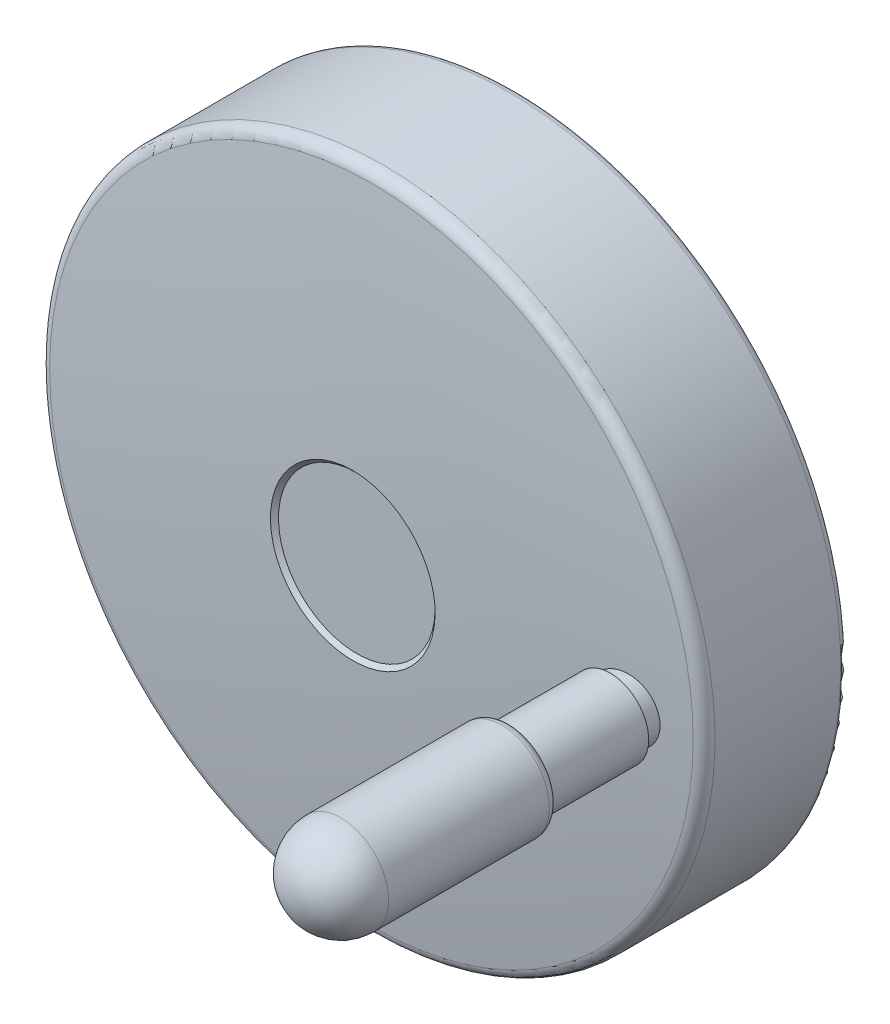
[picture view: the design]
ISO-10303-21;
HEADER;
FILE_DESCRIPTION(('STEP AP214'),'2;1');
FILE_NAME('part.step','',(''),(''),'','','');
FILE_SCHEMA(('AUTOMOTIVE_DESIGN { 1 0 10303 214 1 1 1 1 }'));
ENDSEC;
DATA;
#1=APPLICATION_CONTEXT('core data for automotive mechanical design processes');
#2=APPLICATION_PROTOCOL_DEFINITION('international standard','automotive_design',2000,#1);
#3=PRODUCT_CONTEXT('',#1,'mechanical');
#4=PRODUCT('Part','Part','',(#3));
#5=PRODUCT_RELATED_PRODUCT_CATEGORY('part','',(#4));
#6=PRODUCT_DEFINITION_FORMATION('','',#4);
#7=PRODUCT_DEFINITION_CONTEXT('part definition',#1,'design');
#8=PRODUCT_DEFINITION('design','',#6,#7);
#9=PRODUCT_DEFINITION_SHAPE('','',#8);
#10=(LENGTH_UNIT() NAMED_UNIT(*) SI_UNIT(.MILLI.,.METRE.));
#11=(NAMED_UNIT(*) PLANE_ANGLE_UNIT() SI_UNIT($,.RADIAN.));
#12=(NAMED_UNIT(*) SI_UNIT($,.STERADIAN.) SOLID_ANGLE_UNIT());
#13=UNCERTAINTY_MEASURE_WITH_UNIT(LENGTH_MEASURE(1.E-05),#10,'distance_accuracy_value','');
#14=(GEOMETRIC_REPRESENTATION_CONTEXT(3) GLOBAL_UNCERTAINTY_ASSIGNED_CONTEXT((#13)) GLOBAL_UNIT_ASSIGNED_CONTEXT((#10,
#11,#12)) REPRESENTATION_CONTEXT('',''));
#15=CARTESIAN_POINT('',(0.,0.,0.));
#16=DIRECTION('',(0.,0.,1.));
#17=DIRECTION('',(1.,0.,0.));
#18=AXIS2_PLACEMENT_3D('',#15,#16,#17);
#19=CARTESIAN_POINT('',(0.,0.,42.));
#20=DIRECTION('',(0.,0.,1.));
#21=DIRECTION('',(0.,1.,0.));
#22=AXIS2_PLACEMENT_3D('',#19,#20,#21);
#23=PLANE('',#22);
#24=CARTESIAN_POINT('',(49.,0.,42.));
#25=DIRECTION('',(0.,0.,1.));
#26=DIRECTION('',(0.,1.,0.));
#27=AXIS2_PLACEMENT_3D('',#24,#25,#26);
#28=CIRCLE('',#27,5.4375);
#29=CARTESIAN_POINT('',(49.,5.43749999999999,42.));
#30=VERTEX_POINT('',#29);
#31=EDGE_CURVE('E310',#30,#30,#28,.T.);
#32=ORIENTED_EDGE('',*,*,#31,.F.);
#33=EDGE_LOOP('',(#32));
#34=FACE_BOUND('',#33,.T.);
#35=CARTESIAN_POINT('',(49.,0.,42.));
#36=DIRECTION('',(0.,0.,-1.));
#37=DIRECTION('',(0.,-1.,0.));
#38=AXIS2_PLACEMENT_3D('',#35,#36,#37);
#39=CIRCLE('',#38,6.);
#40=CARTESIAN_POINT('',(49.,-6.,42.));
#41=VERTEX_POINT('',#40);
#42=EDGE_CURVE('E850',#41,#41,#39,.T.);
#43=ORIENTED_EDGE('',*,*,#42,.F.);
#44=EDGE_LOOP('',(#43));
#45=FACE_BOUND('',#44,.T.);
#46=ADVANCED_FACE('F15',(#34,#45),#23,.T.);
#47=CARTESIAN_POINT('',(49.,0.,38.));
#48=DIRECTION('',(0.,0.,-1.));
#49=DIRECTION('',(0.,-1.,0.));
#50=AXIS2_PLACEMENT_3D('',#47,#48,#49);
#51=CYLINDRICAL_SURFACE('',#50,6.);
#52=CARTESIAN_POINT('',(43.,0.,40.1107074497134));
#53=CARTESIAN_POINT('',(43.0000009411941,0.167835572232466,40.1107073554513));
#54=CARTESIAN_POINT('',(43.0070482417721,0.335701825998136,40.110000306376));
#55=CARTESIAN_POINT('',(43.035192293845,0.670274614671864,40.1071766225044));
#56=CARTESIAN_POINT('',(43.0562932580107,0.836980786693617,40.1050595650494));
#57=CARTESIAN_POINT('',(43.1124381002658,1.16828288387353,40.0994264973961));
#58=CARTESIAN_POINT('',(43.1475041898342,1.33287501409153,40.095908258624));
#59=CARTESIAN_POINT('',(43.2313557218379,1.65863013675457,40.0874951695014));
#60=CARTESIAN_POINT('',(43.2801521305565,1.81979027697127,40.0825992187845));
#61=CARTESIAN_POINT('',(43.3909930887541,2.13710869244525,40.0714778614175));
#62=CARTESIAN_POINT('',(43.4530131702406,2.29327560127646,40.065254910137));
#63=CARTESIAN_POINT('',(43.5899340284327,2.5998822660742,40.0515162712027));
#64=CARTESIAN_POINT('',(43.6648406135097,2.75031940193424,40.0440000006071));
#65=CARTESIAN_POINT('',(43.8269764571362,3.04434120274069,40.02773053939));
#66=CARTESIAN_POINT('',(43.9142064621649,3.18792545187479,40.0189772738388));
#67=CARTESIAN_POINT('',(44.1003135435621,3.46716202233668,40.0003014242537));
#68=CARTESIAN_POINT('',(44.1991854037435,3.60281785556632,39.9903793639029));
#69=CARTESIAN_POINT('',(44.4081943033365,3.8656949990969,39.9694040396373));
#70=CARTESIAN_POINT('',(44.5183626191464,3.99289119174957,39.958347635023));
#71=CARTESIAN_POINT('',(44.7488252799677,4.23741820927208,39.9352177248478));
#72=CARTESIAN_POINT('',(44.8691097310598,4.35475845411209,39.9231452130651));
#73=CARTESIAN_POINT('',(45.1190961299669,4.57895044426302,39.8980539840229));
#74=CARTESIAN_POINT('',(45.2488024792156,4.68579723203,39.8850348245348));
#75=CARTESIAN_POINT('',(45.5166911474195,4.88822582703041,39.8581445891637));
#76=CARTESIAN_POINT('',(45.6548754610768,4.9838049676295,39.8442733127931));
#77=CARTESIAN_POINT('',(45.9393374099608,5.16340606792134,39.8157170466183));
#78=CARTESIAN_POINT('',(46.0856479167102,5.24737544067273,39.8010287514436));
#79=CARTESIAN_POINT('',(46.3848184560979,5.40270708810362,39.7709932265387));
#80=CARTESIAN_POINT('',(46.5376808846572,5.47406470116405,39.7556457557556));
#81=CARTESIAN_POINT('',(46.8487652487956,5.60362101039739,39.7244111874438));
#82=CARTESIAN_POINT('',(47.006985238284,5.66182442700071,39.7085242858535));
#83=CARTESIAN_POINT('',(47.3277798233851,5.76472592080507,39.6763116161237));
#84=CARTESIAN_POINT('',(47.4903560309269,5.80941892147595,39.6599856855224));
#85=CARTESIAN_POINT('',(47.8193269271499,5.88511803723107,39.6269486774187));
#86=CARTESIAN_POINT('',(47.985734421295,5.91606794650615,39.6102363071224));
#87=CARTESIAN_POINT('',(48.3206243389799,5.96381333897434,39.5766014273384));
#88=CARTESIAN_POINT('',(48.4891076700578,5.98060239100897,39.5596788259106));
#89=CARTESIAN_POINT('',(48.82688464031,5.99988731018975,39.525750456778));
#90=CARTESIAN_POINT('',(48.996178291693,6.00238296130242,39.5087446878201));
#91=CARTESIAN_POINT('',(49.3342984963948,5.99306555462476,39.4747782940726));
#92=CARTESIAN_POINT('',(49.5031252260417,5.98125895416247,39.4578176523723));
#93=CARTESIAN_POINT('',(49.8396421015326,5.94337840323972,39.4240088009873));
#94=CARTESIAN_POINT('',(50.0073280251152,5.91726655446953,39.4071610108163));
#95=CARTESIAN_POINT('',(50.3398508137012,5.85094280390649,39.3737499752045));
#96=CARTESIAN_POINT('',(50.5046887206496,5.8107361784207,39.3571866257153));
#97=CARTESIAN_POINT('',(50.8304680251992,5.71648072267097,39.3244498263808));
#98=CARTESIAN_POINT('',(50.9914078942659,5.66242655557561,39.3082765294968));
#99=CARTESIAN_POINT('',(51.3081149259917,5.54088114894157,39.276448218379));
#100=CARTESIAN_POINT('',(51.4638839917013,5.47339491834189,39.2607930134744));
#101=CARTESIAN_POINT('',(51.7691010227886,5.32548779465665,39.2301164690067));
#102=CARTESIAN_POINT('',(51.9185528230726,5.24507489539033,39.2150947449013));
#103=CARTESIAN_POINT('',(52.2101278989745,5.07186615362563,39.1857866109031));
#104=CARTESIAN_POINT('',(52.352252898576,4.97907324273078,39.1715000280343));
#105=CARTESIAN_POINT('',(52.6281207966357,4.7817865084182,39.143768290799));
#106=CARTESIAN_POINT('',(52.7618676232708,4.67729823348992,39.1303227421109));
#107=CARTESIAN_POINT('',(53.0202101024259,4.45721140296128,39.1043506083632));
#108=CARTESIAN_POINT('',(53.144796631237,4.34160202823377,39.0918249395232));
#109=CARTESIAN_POINT('',(53.383236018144,4.10071161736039,39.0678518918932));
#110=CARTESIAN_POINT('',(53.4971338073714,3.97547550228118,39.0563999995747));
#111=CARTESIAN_POINT('',(53.7140344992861,3.71571286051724,39.0345909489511));
#112=CARTESIAN_POINT('',(53.8170324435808,3.58118215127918,39.0242342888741));
#113=CARTESIAN_POINT('',(54.0113136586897,3.30384601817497,39.0046983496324));
#114=CARTESIAN_POINT('',(54.1025977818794,3.16104119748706,38.9955189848));
#115=CARTESIAN_POINT('',(54.2727502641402,2.86823346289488,38.9784083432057));
#116=CARTESIAN_POINT('',(54.3516243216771,2.7182338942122,38.9704764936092));
#117=CARTESIAN_POINT('',(54.4961947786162,2.41253808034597,38.9559376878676));
#118=CARTESIAN_POINT('',(54.5619323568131,2.25686150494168,38.949326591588));
#119=CARTESIAN_POINT('',(54.680011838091,1.94060091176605,38.9374513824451));
#120=CARTESIAN_POINT('',(54.732364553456,1.78002097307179,38.9321861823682));
#121=CARTESIAN_POINT('',(54.8232839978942,1.45525129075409,38.9230421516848));
#122=CARTESIAN_POINT('',(54.8618729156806,1.29106781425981,38.9191610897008));
#123=CARTESIAN_POINT('',(54.9250903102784,0.960042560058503,38.9128029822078));
#124=CARTESIAN_POINT('',(54.9497230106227,0.793201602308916,38.9103255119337));
#125=CARTESIAN_POINT('',(54.9781855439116,0.521745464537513,38.9074628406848));
#126=CARTESIAN_POINT('',(54.9863633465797,0.417571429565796,38.9066403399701));
#127=CARTESIAN_POINT('',(54.997270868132,0.208935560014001,38.9055432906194));
#128=CARTESIAN_POINT('',(55.0000005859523,0.104473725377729,38.9052687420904));
#129=CARTESIAN_POINT('',(54.9999990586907,-0.167832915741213,38.905268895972));
#130=CARTESIAN_POINT('',(54.9929519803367,-0.335696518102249,38.9059776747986));
#131=CARTESIAN_POINT('',(54.964808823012,-0.670264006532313,38.9088082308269));
#132=CARTESIAN_POINT('',(54.9437085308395,-0.836967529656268,38.9109304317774));
#133=CARTESIAN_POINT('',(54.8875654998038,-1.16826434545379,38.9165770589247));
#134=CARTESIAN_POINT('',(54.8525005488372,-1.33285384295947,38.9201037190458));
#135=CARTESIAN_POINT('',(54.7686517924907,-1.65860370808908,38.9285366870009));
#136=CARTESIAN_POINT('',(54.7198570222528,-1.81976122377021,38.9334440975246));
#137=CARTESIAN_POINT('',(54.6090199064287,-2.13707433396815,38.9445910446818));
#138=CARTESIAN_POINT('',(54.5470020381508,-2.29323856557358,38.9508281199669));
#139=CARTESIAN_POINT('',(54.4100861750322,-2.59984000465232,38.9645972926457));
#140=CARTESIAN_POINT('',(54.3351823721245,-2.75027459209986,38.9721299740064));
#141=CARTESIAN_POINT('',(54.1730526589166,-3.04429152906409,38.9884340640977));
#142=CARTESIAN_POINT('',(54.0858260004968,-3.18787346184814,38.9972055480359));
#143=CARTESIAN_POINT('',(53.8997261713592,-3.46710571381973,39.0159191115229));
#144=CARTESIAN_POINT('',(53.8008582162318,-3.60275954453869,39.0258606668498));
#145=CARTESIAN_POINT('',(53.5918561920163,-3.86563494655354,39.0468759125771));
#146=CARTESIAN_POINT('',(53.4816906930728,-3.99283127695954,39.0579527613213));
#147=CARTESIAN_POINT('',(53.2512338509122,-4.23735881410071,39.081123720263));
#148=CARTESIAN_POINT('',(53.1309524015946,-4.35469944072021,39.0932168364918));
#149=CARTESIAN_POINT('',(52.8809721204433,-4.57889252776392,39.1183488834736));
#150=CARTESIAN_POINT('',(52.7512688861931,-4.68574002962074,39.131388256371));
#151=CARTESIAN_POINT('',(52.4833864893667,-4.88817043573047,39.158317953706));
#152=CARTESIAN_POINT('',(52.3452053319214,-4.9837506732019,39.1722084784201));
#153=CARTESIAN_POINT('',(52.0607466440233,-5.16335629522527,39.2008021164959));
#154=CARTESIAN_POINT('',(51.9144360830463,-5.24732884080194,39.2155085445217));
#155=CARTESIAN_POINT('',(51.6152650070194,-5.40266673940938,39.2455783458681));
#156=CARTESIAN_POINT('',(51.4624020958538,-5.47402743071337,39.2609419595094));
#157=CARTESIAN_POINT('',(51.1513162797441,-5.6035897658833,39.2922063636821));
#158=CARTESIAN_POINT('',(50.9930953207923,-5.66179612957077,39.3081069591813));
#159=CARTESIAN_POINT('',(50.6722982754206,-5.76470332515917,39.3403442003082));
#160=CARTESIAN_POINT('',(50.5097205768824,-5.80939908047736,39.3566810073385));
#161=CARTESIAN_POINT('',(50.1807455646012,-5.88510357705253,39.3897367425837));
#162=CARTESIAN_POINT('',(50.0143354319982,-5.91605606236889,39.4064569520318));
#163=CARTESIAN_POINT('',(49.679439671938,-5.96380613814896,39.4401041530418));
#164=CARTESIAN_POINT('',(49.5109531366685,-5.98059729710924,39.4570312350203));
#165=CARTESIAN_POINT('',(49.1731692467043,-5.99988585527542,39.4909650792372));
#166=CARTESIAN_POINT('',(49.0038718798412,-6.00238303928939,39.5079718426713));
#167=CARTESIAN_POINT('',(48.6657438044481,-5.99306802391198,39.5419367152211));
#168=CARTESIAN_POINT('',(48.4969129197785,-5.98126228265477,39.5588948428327));
#169=CARTESIAN_POINT('',(48.1603903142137,-5.94338301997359,39.5926949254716));
#170=CARTESIAN_POINT('',(47.992702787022,-5.91727184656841,39.6095364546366));
#171=CARTESIAN_POINT('',(47.6601764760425,-5.85094910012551,39.6429316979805));
#172=CARTESIAN_POINT('',(47.4953366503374,-5.81074280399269,39.6594855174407));
#173=CARTESIAN_POINT('',(47.1695533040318,-5.71648760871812,39.6922002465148));
#174=CARTESIAN_POINT('',(47.0086113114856,-5.66243337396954,39.7083610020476));
#175=CARTESIAN_POINT('',(46.6918999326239,-5.54088740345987,39.7401615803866));
#176=CARTESIAN_POINT('',(46.5361286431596,-5.47340067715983,39.7558015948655));
#177=CARTESIAN_POINT('',(46.230910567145,-5.32549377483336,39.7864452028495));
#178=CARTESIAN_POINT('',(46.0814598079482,-5.24508187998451,39.8014491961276));
#179=CARTESIAN_POINT('',(45.7898866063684,-5.07187528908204,39.8307201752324));
#180=CARTESIAN_POINT('',(45.6477624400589,-4.9790835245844,39.8449873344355));
#181=CARTESIAN_POINT('',(45.3718960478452,-4.78179924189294,39.8726790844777));
#182=CARTESIAN_POINT('',(45.2381498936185,-4.6773122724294,39.8861040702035));
#183=CARTESIAN_POINT('',(44.979808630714,-4.45722824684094,39.9120344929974));
#184=CARTESIAN_POINT('',(44.8552226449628,-4.34162037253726,39.9245390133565));
#185=CARTESIAN_POINT('',(44.6167849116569,-4.10073388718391,39.9484698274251));
#186=CARTESIAN_POINT('',(44.5028881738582,-3.97550025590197,39.9599006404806));
#187=CARTESIAN_POINT('',(44.285989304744,-3.71574294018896,39.9816681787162));
#188=CARTESIAN_POINT('',(44.1829921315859,-3.5812150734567,39.9920044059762));
#189=CARTESIAN_POINT('',(43.9887121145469,-3.30388496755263,40.0115007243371));
#190=CARTESIAN_POINT('',(43.8974284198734,-3.16108333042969,40.0206609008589));
#191=CARTESIAN_POINT('',(43.727276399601,-2.86828230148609,40.0377349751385));
#192=CARTESIAN_POINT('',(43.6484023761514,-2.71828625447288,40.0456494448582));
#193=CARTESIAN_POINT('',(43.5038303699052,-2.41259533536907,40.0601559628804));
#194=CARTESIAN_POINT('',(43.4380914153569,-2.25692003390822,40.0667521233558));
#195=CARTESIAN_POINT('',(43.3200090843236,-1.9406620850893,40.0786001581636));
#196=CARTESIAN_POINT('',(43.2676548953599,-1.78008351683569,40.083853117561));
#197=CARTESIAN_POINT('',(43.1767323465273,-1.45531658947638,40.0929757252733));
#198=CARTESIAN_POINT('',(43.1381418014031,-1.29113449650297,40.0968475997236));
#199=CARTESIAN_POINT('',(43.0749209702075,-0.960111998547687,40.1031906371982));
#200=CARTESIAN_POINT('',(43.0502864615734,-0.793272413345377,40.1056622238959));
#201=CARTESIAN_POINT('',(43.0218195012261,-0.521805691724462,40.108518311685));
#202=CARTESIAN_POINT('',(43.0136398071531,-0.417619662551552,40.1093389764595));
#203=CARTESIAN_POINT('',(43.0027297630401,-0.208959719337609,40.1104335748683));
#204=CARTESIAN_POINT('',(42.9999994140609,-0.104485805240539,40.1107075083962));
#205=CARTESIAN_POINT('',(43.,0.,40.1107074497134));
#206=B_SPLINE_CURVE_WITH_KNOTS('',3,(#52,#53,#54,#55,#56,#57,#58,#59,#60,#61,#62,#63,#64,#65,
#66,#67,#68,#69,#70,#71,#72,#73,#74,#75,#76,#77,#78,#79,#80,#81,#82,#83,#84,#85,#86,#87,#88,#89,
#90,#91,#92,#93,#94,#95,#96,#97,#98,#99,#100,#101,#102,#103,#104,#105,#106,#107,#108,#109,#110,
#111,#112,#113,#114,#115,#116,#117,#118,#119,#120,#121,#122,#123,#124,#125,#126,#127,#128,#129,
#130,#131,#132,#133,#134,#135,#136,#137,#138,#139,#140,#141,#142,#143,#144,#145,#146,#147,#148,
#149,#150,#151,#152,#153,#154,#155,#156,#157,#158,#159,#160,#161,#162,#163,#164,#165,#166,#167,
#168,#169,#170,#171,#172,#173,#174,#175,#176,#177,#178,#179,#180,#181,#182,#183,#184,#185,#186,
#187,#188,#189,#190,#191,#192,#193,#194,#195,#196,#197,#198,#199,#200,#201,#202,#203,#204,#205),
.UNSPECIFIED.,.T.,.F.,(4,2,2,2,2,2,2,2,2,2,2,2,2,2,2,2,2,2,2,2,2,2,2,2,2,2,2,2,2,2,2,2,2,2,2,2,
2,2,2,2,2,2,2,2,2,2,2,2,2,2,2,2,2,2,2,2,2,2,2,2,2,2,2,2,2,2,2,2,2,2,2,2,2,2,2,2,4),(0.,
0.50341075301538,1.00697247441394,1.51133832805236,2.01610816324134,2.51995199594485,
3.02402352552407,3.52812560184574,4.03200266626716,4.5373145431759,5.04213783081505,
5.54719848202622,6.05237842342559,6.55977646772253,7.06736166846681,7.57476443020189,
8.08235761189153,8.59200802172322,9.10188976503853,9.6117792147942,10.1214385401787,
10.6324546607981,11.1432796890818,11.6543018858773,12.1651338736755,12.6756511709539,
13.1860477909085,13.6962032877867,14.2068602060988,14.7152641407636,15.223898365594,
15.7324955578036,16.2408585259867,16.7476020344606,17.2539348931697,17.7594477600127,
18.2648075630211,18.5781689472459,18.8915303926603,19.3949331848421,19.8984869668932,
20.4028449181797,20.9076068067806,21.4114423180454,21.9155055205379,22.419599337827,
22.9234681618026,23.4287788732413,23.9336009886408,24.4386605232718,24.9438393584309,
25.4512469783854,25.9588417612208,26.4662541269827,26.9738569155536,27.4835187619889,
27.9934119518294,28.503312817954,29.0129835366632,29.5240022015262,30.0348297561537,
30.5458544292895,31.0566888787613,31.5671973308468,32.077585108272,32.587731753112,
33.0983797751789,33.6067718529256,34.1153942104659,34.6239796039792,35.1323307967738,
35.6390706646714,36.145399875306,36.6509092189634,37.1562655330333,37.4696631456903,
37.7830608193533),.UNSPECIFIED.);
#207=CARTESIAN_POINT('',(43.,0.,40.1107074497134));
#208=VERTEX_POINT('',#207);
#209=EDGE_CURVE('E337',#208,#208,#206,.T.);
#210=ORIENTED_EDGE('',*,*,#209,.F.);
#211=EDGE_LOOP('',(#210));
#212=FACE_BOUND('',#211,.T.);
#213=ORIENTED_EDGE('',*,*,#42,.T.);
#214=EDGE_LOOP('',(#213));
#215=FACE_BOUND('',#214,.T.);
#216=ADVANCED_FACE('F332',(#212,#215),#51,.T.);
#217=CARTESIAN_POINT('',(0.,0.,-448.281250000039));
#218=DIRECTION('',(-1.,0.,0.));
#219=DIRECTION('',(0.,0.,1.));
#220=AXIS2_PLACEMENT_3D('',#217,#218,#219);
#221=SPHERICAL_SURFACE('',#220,490.281250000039);
#222=CARTESIAN_POINT('',(0.,0.,38.2439407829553));
#223=DIRECTION('',(0.,0.,1.));
#224=DIRECTION('',(0.,1.,0.));
#225=AXIS2_PLACEMENT_3D('',#222,#223,#224);
#226=CIRCLE('',#225,60.571799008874);
#227=CARTESIAN_POINT('',(0.,60.571799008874,38.2439407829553));
#228=VERTEX_POINT('',#227);
#229=EDGE_CURVE('E304',#228,#228,#226,.T.);
#230=ORIENTED_EDGE('',*,*,#229,.T.);
#231=EDGE_LOOP('',(#230));
#232=FACE_BOUND('',#231,.T.);
#233=CARTESIAN_POINT('',(0.,0.,41.7549263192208));
#234=DIRECTION('',(0.,0.,1.));
#235=DIRECTION('',(0.,1.,0.));
#236=AXIS2_PLACEMENT_3D('',#233,#234,#235);
#237=CIRCLE('',#236,15.5);
#238=CARTESIAN_POINT('',(0.,15.5,41.7549263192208));
#239=VERTEX_POINT('',#238);
#240=EDGE_CURVE('E345',#239,#239,#237,.F.);
#241=ORIENTED_EDGE('',*,*,#240,.T.);
#242=EDGE_LOOP('',(#241));
#243=FACE_BOUND('',#242,.T.);
#244=ORIENTED_EDGE('',*,*,#209,.T.);
#245=EDGE_LOOP('',(#244));
#246=FACE_BOUND('',#245,.T.);
#247=ADVANCED_FACE('F326',(#232,#243,#246),#221,.T.);
#248=CARTESIAN_POINT('',(0.,0.,36.0607950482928));
#249=DIRECTION('',(0.,0.,1.));
#250=DIRECTION('',(0.,1.,0.));
#251=AXIS2_PLACEMENT_3D('',#248,#249,#250);
#252=TOROIDAL_SURFACE('',#251,60.3,2.2);
#253=CARTESIAN_POINT('',(0.,0.,36.0607950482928));
#254=DIRECTION('',(0.,0.,1.));
#255=DIRECTION('',(0.,1.,0.));
#256=AXIS2_PLACEMENT_3D('',#253,#254,#255);
#257=CIRCLE('',#256,62.5);
#258=CARTESIAN_POINT('',(0.,62.5,36.0607950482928));
#259=VERTEX_POINT('',#258);
#260=EDGE_CURVE('E346',#259,#259,#257,.T.);
#261=ORIENTED_EDGE('',*,*,#260,.T.);
#262=EDGE_LOOP('',(#261));
#263=FACE_BOUND('',#262,.T.);
#264=ORIENTED_EDGE('',*,*,#229,.F.);
#265=EDGE_LOOP('',(#264));
#266=FACE_BOUND('',#265,.T.);
#267=ADVANCED_FACE('F331',(#263,#266),#252,.T.);
#268=CARTESIAN_POINT('',(0.,0.,41.7549263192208));
#269=DIRECTION('',(0.,0.,1.));
#270=DIRECTION('',(0.,1.,0.));
#271=AXIS2_PLACEMENT_3D('',#268,#269,#270);
#272=CONICAL_SURFACE('',#271,15.5,0.785398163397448);
#273=CARTESIAN_POINT('',(0.,0.,41.));
#274=DIRECTION('',(0.,0.,1.));
#275=DIRECTION('',(0.,1.,0.));
#276=AXIS2_PLACEMENT_3D('',#273,#274,#275);
#277=CIRCLE('',#276,14.7450736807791);
#278=CARTESIAN_POINT('',(0.,14.7450736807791,41.));
#279=VERTEX_POINT('',#278);
#280=EDGE_CURVE('E348',#279,#279,#277,.T.);
#281=ORIENTED_EDGE('',*,*,#280,.F.);
#282=EDGE_LOOP('',(#281));
#283=FACE_BOUND('',#282,.T.);
#284=ORIENTED_EDGE('',*,*,#240,.F.);
#285=EDGE_LOOP('',(#284));
#286=FACE_BOUND('',#285,.T.);
#287=ADVANCED_FACE('F354',(#283,#286),#272,.F.);
#288=CARTESIAN_POINT('',(0.,0.,24.2178975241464));
#289=DIRECTION('',(0.,0.,-1.));
#290=DIRECTION('',(0.,-1.,0.));
#291=AXIS2_PLACEMENT_3D('',#288,#289,#290);
#292=CYLINDRICAL_SURFACE('',#291,62.5);
#293=CARTESIAN_POINT('',(0.,0.,12.375));
#294=DIRECTION('',(0.,0.,-1.));
#295=DIRECTION('',(0.,-1.,0.));
#296=AXIS2_PLACEMENT_3D('',#293,#294,#295);
#297=CIRCLE('',#296,62.5);
#298=CARTESIAN_POINT('',(0.,-62.5,12.375));
#299=VERTEX_POINT('',#298);
#300=EDGE_CURVE('E64',#299,#299,#297,.F.);
#301=ORIENTED_EDGE('',*,*,#300,.T.);
#302=EDGE_LOOP('',(#301));
#303=FACE_BOUND('',#302,.T.);
#304=ORIENTED_EDGE('',*,*,#260,.F.);
#305=EDGE_LOOP('',(#304));
#306=FACE_BOUND('',#305,.T.);
#307=ADVANCED_FACE('F355',(#303,#306),#292,.T.);
#308=CARTESIAN_POINT('',(-7.37253684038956,0.,41.));
#309=DIRECTION('',(0.,0.,1.));
#310=DIRECTION('',(0.,1.,0.));
#311=AXIS2_PLACEMENT_3D('',#308,#309,#310);
#312=PLANE('',#311);
#313=ORIENTED_EDGE('',*,*,#280,.T.);
#314=EDGE_LOOP('',(#313));
#315=FACE_BOUND('',#314,.T.);
#316=ADVANCED_FACE('F85',(#315),#312,.T.);
#317=CARTESIAN_POINT('',(0.,0.,12.375));
#318=DIRECTION('',(0.,0.,1.));
#319=DIRECTION('',(0.,1.,0.));
#320=AXIS2_PLACEMENT_3D('',#317,#318,#319);
#321=TOROIDAL_SURFACE('',#320,61.125,1.375);
#322=ORIENTED_EDGE('',*,*,#300,.F.);
#323=EDGE_LOOP('',(#322));
#324=FACE_BOUND('',#323,.T.);
#325=CARTESIAN_POINT('',(0.,0.,11.));
#326=DIRECTION('',(0.,0.,1.));
#327=DIRECTION('',(0.,-1.,0.));
#328=AXIS2_PLACEMENT_3D('',#325,#326,#327);
#329=CIRCLE('',#328,61.125);
#330=CARTESIAN_POINT('',(0.,-61.125,11.));
#331=VERTEX_POINT('',#330);
#332=CARTESIAN_POINT('',(0.,61.125,11.));
#333=VERTEX_POINT('',#332);
#334=EDGE_CURVE('E54',#331,#333,#329,.T.);
#335=ORIENTED_EDGE('',*,*,#334,.T.);
#336=CARTESIAN_POINT('',(0.,0.,11.));
#337=DIRECTION('',(0.,0.,1.));
#338=DIRECTION('',(0.,1.,0.));
#339=AXIS2_PLACEMENT_3D('',#336,#337,#338);
#340=CIRCLE('',#339,61.125);
#341=CARTESIAN_POINT('',(-61.125,0.,11.));
#342=VERTEX_POINT('',#341);
#343=EDGE_CURVE('E50',#333,#342,#340,.T.);
#344=ORIENTED_EDGE('',*,*,#343,.T.);
#345=CARTESIAN_POINT('',(0.,0.,11.));
#346=DIRECTION('',(0.,0.,1.));
#347=DIRECTION('',(-1.,0.,0.));
#348=AXIS2_PLACEMENT_3D('',#345,#346,#347);
#349=CIRCLE('',#348,61.125);
#350=EDGE_CURVE('E47',#342,#331,#349,.T.);
#351=ORIENTED_EDGE('',*,*,#350,.T.);
#352=EDGE_LOOP('',(#335,#344,#351));
#353=FACE_BOUND('',#352,.T.);
#354=ADVANCED_FACE('F62',(#324,#353),#321,.T.);
#355=CARTESIAN_POINT('',(-60.5625,0.,11.));
#356=DIRECTION('',(0.,0.,-1.));
#357=DIRECTION('',(-1.,0.,0.));
#358=AXIS2_PLACEMENT_3D('',#355,#356,#357);
#359=PLANE('',#358);
#360=CARTESIAN_POINT('',(0.,0.,11.));
#361=DIRECTION('',(0.,0.,-1.));
#362=DIRECTION('',(0.,-1.,0.));
#363=AXIS2_PLACEMENT_3D('',#360,#361,#362);
#364=CIRCLE('',#363,60.);
#365=CARTESIAN_POINT('',(0.,-60.,11.));
#366=VERTEX_POINT('',#365);
#367=EDGE_CURVE('E854',#366,#366,#364,.F.);
#368=ORIENTED_EDGE('',*,*,#367,.T.);
#369=EDGE_LOOP('',(#368));
#370=FACE_BOUND('',#369,.T.);
#371=ORIENTED_EDGE('',*,*,#343,.F.);
#372=ORIENTED_EDGE('',*,*,#334,.F.);
#373=ORIENTED_EDGE('',*,*,#350,.F.);
#374=EDGE_LOOP('',(#371,#372,#373));
#375=FACE_BOUND('',#374,.T.);
#376=ADVANCED_FACE('F53',(#370,#375),#359,.T.);
#377=CARTESIAN_POINT('',(0.,0.,13.9));
#378=DIRECTION('',(0.,0.,-1.));
#379=DIRECTION('',(0.,-1.,0.));
#380=AXIS2_PLACEMENT_3D('',#377,#378,#379);
#381=CYLINDRICAL_SURFACE('',#380,60.);
#382=ORIENTED_EDGE('',*,*,#367,.F.);
#383=EDGE_LOOP('',(#382));
#384=FACE_BOUND('',#383,.T.);
#385=CARTESIAN_POINT('',(0.,0.,16.8));
#386=DIRECTION('',(0.,0.,-1.));
#387=DIRECTION('',(0.,-1.,0.));
#388=AXIS2_PLACEMENT_3D('',#385,#386,#387);
#389=CIRCLE('',#388,60.);
#390=CARTESIAN_POINT('',(0.,-60.,16.8));
#391=VERTEX_POINT('',#390);
#392=EDGE_CURVE('E861',#391,#391,#389,.T.);
#393=ORIENTED_EDGE('',*,*,#392,.F.);
#394=EDGE_LOOP('',(#393));
#395=FACE_BOUND('',#394,.T.);
#396=ADVANCED_FACE('F104',(#384,#395),#381,.F.);
#397=CARTESIAN_POINT('',(49.,0.,31.5));
#398=DIRECTION('',(0.,0.,1.));
#399=DIRECTION('',(0.,1.,0.));
#400=AXIS2_PLACEMENT_3D('',#397,#398,#399);
#401=CYLINDRICAL_SURFACE('',#400,2.4585);
#402=CARTESIAN_POINT('',(49.,0.,29.0719999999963));
#403=DIRECTION('',(0.,0.,1.));
#404=DIRECTION('',(1.,0.,0.));
#405=AXIS2_PLACEMENT_3D('',#402,#403,#404);
#406=CIRCLE('',#405,2.4585);
#407=CARTESIAN_POINT('',(51.4585,0.,29.0719999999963));
#408=VERTEX_POINT('',#407);
#409=EDGE_CURVE('E26',#408,#408,#406,.F.);
#410=ORIENTED_EDGE('',*,*,#409,.F.);
#411=EDGE_LOOP('',(#410));
#412=FACE_BOUND('',#411,.T.);
#413=CARTESIAN_POINT('',(49.,0.,21.5415));
#414=DIRECTION('',(0.,0.,1.));
#415=DIRECTION('',(0.,1.,0.));
#416=AXIS2_PLACEMENT_3D('',#413,#414,#415);
#417=CIRCLE('',#416,2.4585);
#418=CARTESIAN_POINT('',(49.,2.4585,21.5415));
#419=VERTEX_POINT('',#418);
#420=EDGE_CURVE('E857',#419,#419,#417,.T.);
#421=ORIENTED_EDGE('',*,*,#420,.F.);
#422=EDGE_LOOP('',(#421));
#423=FACE_BOUND('',#422,.T.);
#424=ADVANCED_FACE('F120',(#412,#423),#401,.F.);
#425=CARTESIAN_POINT('',(49.,0.,21.0000000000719));
#426=DIRECTION('',(0.,0.,-1.));
#427=DIRECTION('',(0.,-1.,0.));
#428=AXIS2_PLACEMENT_3D('',#425,#426,#427);
#429=CONICAL_SURFACE('',#428,2.99999999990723,0.785398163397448);
#430=ORIENTED_EDGE('',*,*,#420,.T.);
#431=EDGE_LOOP('',(#430));
#432=FACE_BOUND('',#431,.T.);
#433=CARTESIAN_POINT('',(49.,0.,21.000000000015));
#434=DIRECTION('',(0.,0.,-1.));
#435=DIRECTION('',(0.,-1.,0.));
#436=AXIS2_PLACEMENT_3D('',#433,#434,#435);
#437=CIRCLE('',#436,2.99999999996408);
#438=CARTESIAN_POINT('',(49.,-2.99999999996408,21.000000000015));
#439=VERTEX_POINT('',#438);
#440=EDGE_CURVE('E858',#439,#439,#437,.F.);
#441=ORIENTED_EDGE('',*,*,#440,.F.);
#442=EDGE_LOOP('',(#441));
#443=FACE_BOUND('',#442,.T.);
#444=ADVANCED_FACE('F125',(#432,#443),#429,.F.);
#445=CARTESIAN_POINT('',(52.3,0.,21.));
#446=DIRECTION('',(0.,0.,1.));
#447=DIRECTION('',(0.,1.,0.));
#448=AXIS2_PLACEMENT_3D('',#445,#446,#447);
#449=PLANE('',#448);
#450=ORIENTED_EDGE('',*,*,#440,.T.);
#451=EDGE_LOOP('',(#450));
#452=FACE_BOUND('',#451,.T.);
#453=CARTESIAN_POINT('',(49.,0.,21.));
#454=DIRECTION('',(0.,0.,1.));
#455=DIRECTION('',(0.,1.,0.));
#456=AXIS2_PLACEMENT_3D('',#453,#454,#455);
#457=CIRCLE('',#456,3.6);
#458=CARTESIAN_POINT('',(49.,3.6,21.));
#459=VERTEX_POINT('',#458);
#460=EDGE_CURVE('E863',#459,#459,#457,.T.);
#461=ORIENTED_EDGE('',*,*,#460,.F.);
#462=EDGE_LOOP('',(#461));
#463=FACE_BOUND('',#462,.T.);
#464=ADVANCED_FACE('F128',(#452,#463),#449,.F.);
#465=CARTESIAN_POINT('',(49.,0.,10.5));
#466=DIRECTION('',(0.,0.,1.));
#467=DIRECTION('',(0.,1.,0.));
#468=AXIS2_PLACEMENT_3D('',#465,#466,#467);
#469=CYLINDRICAL_SURFACE('',#468,3.6);
#470=CARTESIAN_POINT('',(49.,0.,16.8));
#471=DIRECTION('',(0.,0.,1.));
#472=DIRECTION('',(0.,1.,0.));
#473=AXIS2_PLACEMENT_3D('',#470,#471,#472);
#474=CIRCLE('',#473,3.6);
#475=CARTESIAN_POINT('',(49.,3.6,16.8));
#476=VERTEX_POINT('',#475);
#477=EDGE_CURVE('E867',#476,#476,#474,.T.);
#478=ORIENTED_EDGE('',*,*,#477,.F.);
#479=EDGE_LOOP('',(#478));
#480=FACE_BOUND('',#479,.T.);
#481=ORIENTED_EDGE('',*,*,#460,.T.);
#482=EDGE_LOOP('',(#481));
#483=FACE_BOUND('',#482,.T.);
#484=ADVANCED_FACE('F138',(#480,#483),#469,.F.);
#485=CARTESIAN_POINT('',(-50.2583644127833,0.,16.8));
#486=DIRECTION('',(0.,0.,-1.));
#487=DIRECTION('',(0.,-1.,0.));
#488=AXIS2_PLACEMENT_3D('',#485,#486,#487);
#489=PLANE('',#488);
#490=CARTESIAN_POINT('',(0.,0.,16.8));
#491=DIRECTION('',(0.,0.,-1.));
#492=DIRECTION('',(0.,-1.,0.));
#493=AXIS2_PLACEMENT_3D('',#490,#491,#492);
#494=CIRCLE('',#493,43.5);
#495=CARTESIAN_POINT('',(0.,-43.5,16.8));
#496=VERTEX_POINT('',#495);
#497=EDGE_CURVE('E716',#496,#496,#494,.F.);
#498=ORIENTED_EDGE('',*,*,#497,.T.);
#499=EDGE_LOOP('',(#498));
#500=FACE_BOUND('',#499,.T.);
#501=CARTESIAN_POINT('',(0.,0.,16.8));
#502=DIRECTION('',(0.,0.,1.));
#503=DIRECTION('',(0.,1.,0.));
#504=AXIS2_PLACEMENT_3D('',#501,#502,#503);
#505=CIRCLE('',#504,57.0167288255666);
#506=CARTESIAN_POINT('',(0.,57.0167288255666,16.8));
#507=VERTEX_POINT('',#506);
#508=EDGE_CURVE('E869',#507,#507,#505,.T.);
#509=ORIENTED_EDGE('',*,*,#508,.F.);
#510=EDGE_LOOP('',(#509));
#511=FACE_BOUND('',#510,.T.);
#512=ORIENTED_EDGE('',*,*,#477,.T.);
#513=EDGE_LOOP('',(#512));
#514=FACE_BOUND('',#513,.T.);
#515=ADVANCED_FACE('F147',(#500,#511,#514),#489,.T.);
#516=CARTESIAN_POINT('',(0.,0.,16.8));
#517=DIRECTION('',(0.,0.,-1.));
#518=DIRECTION('',(0.,-1.,0.));
#519=AXIS2_PLACEMENT_3D('',#516,#517,#518);
#520=CONICAL_SURFACE('',#519,43.5,0.785398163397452);
#521=ORIENTED_EDGE('',*,*,#497,.F.);
#522=EDGE_LOOP('',(#521));
#523=FACE_BOUND('',#522,.T.);
#524=CARTESIAN_POINT('',(0.,0.,17.8));
#525=DIRECTION('',(0.,0.,-1.));
#526=DIRECTION('',(-1.,0.,0.));
#527=AXIS2_PLACEMENT_3D('',#524,#525,#526);
#528=CIRCLE('',#527,42.5);
#529=CARTESIAN_POINT('',(-42.5,0.,17.8));
#530=VERTEX_POINT('',#529);
#531=EDGE_CURVE('E874',#530,#530,#528,.T.);
#532=ORIENTED_EDGE('',*,*,#531,.F.);
#533=EDGE_LOOP('',(#532));
#534=FACE_BOUND('',#533,.T.);
#535=ADVANCED_FACE('F152',(#523,#534),#520,.F.);
#536=CARTESIAN_POINT('',(0.,0.,29.4675974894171));
#537=DIRECTION('',(0.,0.,1.));
#538=DIRECTION('',(0.,1.,0.));
#539=AXIS2_PLACEMENT_3D('',#536,#537,#538);
#540=CONICAL_SURFACE('',#539,58.125,0.0872664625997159);
#541=CARTESIAN_POINT('',(0.,0.,29.4675974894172));
#542=DIRECTION('',(0.,0.,-1.));
#543=DIRECTION('',(-1.,0.,0.));
#544=AXIS2_PLACEMENT_3D('',#541,#542,#543);
#545=CIRCLE('',#544,58.125);
#546=CARTESIAN_POINT('',(-58.125,0.,29.4675974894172));
#547=VERTEX_POINT('',#546);
#548=EDGE_CURVE('E866',#547,#547,#545,.T.);
#549=ORIENTED_EDGE('',*,*,#548,.T.);
#550=EDGE_LOOP('',(#549));
#551=FACE_BOUND('',#550,.T.);
#552=ORIENTED_EDGE('',*,*,#508,.T.);
#553=EDGE_LOOP('',(#552));
#554=FACE_BOUND('',#553,.T.);
#555=ADVANCED_FACE('F149',(#551,#554),#540,.T.);
#556=CARTESIAN_POINT('',(0.,0.,23.5575592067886));
#557=DIRECTION('',(0.,0.,-1.));
#558=DIRECTION('',(0.,-1.,0.));
#559=AXIS2_PLACEMENT_3D('',#556,#557,#558);
#560=CYLINDRICAL_SURFACE('',#559,42.5);
#561=ORIENTED_EDGE('',*,*,#531,.T.);
#562=EDGE_LOOP('',(#561));
#563=FACE_BOUND('',#562,.T.);
#564=CARTESIAN_POINT('',(0.,0.,29.3151184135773));
#565=DIRECTION('',(0.,0.,-1.));
#566=DIRECTION('',(0.,-1.,0.));
#567=AXIS2_PLACEMENT_3D('',#564,#565,#566);
#568=CIRCLE('',#567,42.5);
#569=CARTESIAN_POINT('',(0.,-42.5,29.3151184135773));
#570=VERTEX_POINT('',#569);
#571=EDGE_CURVE('E171',#570,#570,#568,.T.);
#572=ORIENTED_EDGE('',*,*,#571,.F.);
#573=EDGE_LOOP('',(#572));
#574=FACE_BOUND('',#573,.T.);
#575=ADVANCED_FACE('F143',(#563,#574),#560,.F.);
#576=CARTESIAN_POINT('',(0.,0.,29.4));
#577=DIRECTION('',(0.,0.,-1.));
#578=DIRECTION('',(0.,-1.,0.));
#579=AXIS2_PLACEMENT_3D('',#576,#577,#578);
#580=CONICAL_SURFACE('',#579,58.8976428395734,1.48352986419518);
#581=CARTESIAN_POINT('',(0.,0.,29.4));
#582=DIRECTION('',(0.,0.,-1.));
#583=DIRECTION('',(-1.,0.,0.));
#584=AXIS2_PLACEMENT_3D('',#581,#582,#583);
#585=CIRCLE('',#584,58.8976428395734);
#586=CARTESIAN_POINT('',(-58.8976428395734,0.,29.4000000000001));
#587=VERTEX_POINT('',#586);
#588=EDGE_CURVE('E862',#587,#587,#585,.T.);
#589=ORIENTED_EDGE('',*,*,#588,.T.);
#590=EDGE_LOOP('',(#589));
#591=FACE_BOUND('',#590,.T.);
#592=ORIENTED_EDGE('',*,*,#548,.F.);
#593=EDGE_LOOP('',(#592));
#594=FACE_BOUND('',#593,.T.);
#595=ADVANCED_FACE('F140',(#591,#594),#580,.F.);
#596=CARTESIAN_POINT('',(0.,0.,29.3151184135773));
#597=DIRECTION('',(0.,0.,1.));
#598=DIRECTION('',(0.,1.,0.));
#599=AXIS2_PLACEMENT_3D('',#596,#597,#598);
#600=TOROIDAL_SURFACE('',#599,40.6666666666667,1.83333333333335);
#601=CARTESIAN_POINT('',(0.,0.,31.1205992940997));
#602=DIRECTION('',(0.,0.,1.));
#603=DIRECTION('',(0.,1.,0.));
#604=AXIS2_PLACEMENT_3D('',#601,#602,#603);
#605=CIRCLE('',#604,40.3483116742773);
#606=CARTESIAN_POINT('',(0.,40.3483116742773,31.1205992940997));
#607=VERTEX_POINT('',#606);
#608=EDGE_CURVE('E173',#607,#607,#605,.F.);
#609=ORIENTED_EDGE('',*,*,#608,.F.);
#610=EDGE_LOOP('',(#609));
#611=FACE_BOUND('',#610,.T.);
#612=ORIENTED_EDGE('',*,*,#571,.T.);
#613=EDGE_LOOP('',(#612));
#614=FACE_BOUND('',#613,.T.);
#615=ADVANCED_FACE('F134',(#611,#614),#600,.F.);
#616=CARTESIAN_POINT('',(0.,0.,16.8));
#617=DIRECTION('',(0.,0.,-1.));
#618=DIRECTION('',(0.,-1.,0.));
#619=AXIS2_PLACEMENT_3D('',#616,#617,#618);
#620=CONICAL_SURFACE('',#619,60.,0.0872664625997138);
#621=ORIENTED_EDGE('',*,*,#392,.T.);
#622=EDGE_LOOP('',(#621));
#623=FACE_BOUND('',#622,.T.);
#624=ORIENTED_EDGE('',*,*,#588,.F.);
#625=EDGE_LOOP('',(#624));
#626=FACE_BOUND('',#625,.T.);
#627=ADVANCED_FACE('F130',(#623,#626),#620,.F.);
#628=CARTESIAN_POINT('',(0.,0.,31.1205992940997));
#629=DIRECTION('',(0.,0.,1.));
#630=DIRECTION('',(0.,1.,0.));
#631=AXIS2_PLACEMENT_3D('',#628,#629,#630);
#632=CONICAL_SURFACE('',#631,40.3483116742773,1.39626340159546);
#633=CARTESIAN_POINT('',(0.,0.,27.2521044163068));
#634=DIRECTION('',(0.,0.,1.));
#635=DIRECTION('',(-1.,0.,0.));
#636=AXIS2_PLACEMENT_3D('',#633,#634,#635);
#637=CIRCLE('',#636,18.4089870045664);
#638=CARTESIAN_POINT('',(-18.4089870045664,0.,27.2521044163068));
#639=VERTEX_POINT('',#638);
#640=EDGE_CURVE('E176',#639,#639,#637,.T.);
#641=ORIENTED_EDGE('',*,*,#640,.T.);
#642=EDGE_LOOP('',(#641));
#643=FACE_BOUND('',#642,.T.);
#644=ORIENTED_EDGE('',*,*,#608,.T.);
#645=EDGE_LOOP('',(#644));
#646=FACE_BOUND('',#645,.T.);
#647=ADVANCED_FACE('F133',(#643,#646),#632,.T.);
#648=CARTESIAN_POINT('',(0.,0.,26.1688158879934));
#649=DIRECTION('',(0.,0.,1.));
#650=DIRECTION('',(0.,1.,0.));
#651=AXIS2_PLACEMENT_3D('',#648,#649,#650);
#652=TOROIDAL_SURFACE('',#651,18.6,1.1);
#653=CARTESIAN_POINT('',(0.,0.,26.1688158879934));
#654=DIRECTION('',(0.,0.,1.));
#655=DIRECTION('',(0.,1.,0.));
#656=AXIS2_PLACEMENT_3D('',#653,#654,#655);
#657=CIRCLE('',#656,17.5);
#658=CARTESIAN_POINT('',(0.,17.5,26.1688158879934));
#659=VERTEX_POINT('',#658);
#660=EDGE_CURVE('E179',#659,#659,#657,.F.);
#661=ORIENTED_EDGE('',*,*,#660,.F.);
#662=EDGE_LOOP('',(#661));
#663=FACE_BOUND('',#662,.T.);
#664=ORIENTED_EDGE('',*,*,#640,.F.);
#665=EDGE_LOOP('',(#664));
#666=FACE_BOUND('',#665,.T.);
#667=ADVANCED_FACE('F183',(#663,#666),#652,.F.);
#668=CARTESIAN_POINT('',(0.,0.,13.1844079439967));
#669=DIRECTION('',(0.,0.,-1.));
#670=DIRECTION('',(0.,-1.,0.));
#671=AXIS2_PLACEMENT_3D('',#668,#669,#670);
#672=CYLINDRICAL_SURFACE('',#671,17.5);
#673=CARTESIAN_POINT('',(17.5,0.,2.));
#674=CARTESIAN_POINT('',(17.4999970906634,0.167197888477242,2.00000663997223));
#675=CARTESIAN_POINT('',(17.4975789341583,0.334485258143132,2.0140247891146));
#676=CARTESIAN_POINT('',(17.4881653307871,0.664363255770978,2.0697009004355));
#677=CARTESIAN_POINT('',(17.4811657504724,0.826949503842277,2.11138382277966));
#678=CARTESIAN_POINT('',(17.4633739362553,1.14260529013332,2.22108991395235));
#679=CARTESIAN_POINT('',(17.4525848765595,1.29568266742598,2.2890910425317));
#680=CARTESIAN_POINT('',(17.4283986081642,1.58823673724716,2.44944444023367));
#681=CARTESIAN_POINT('',(17.4150016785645,1.72771488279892,2.54179410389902));
#682=CARTESIAN_POINT('',(17.3869322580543,1.99053687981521,2.74921385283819));
#683=CARTESIAN_POINT('',(17.3722493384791,2.11372361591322,2.86448162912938));
#684=CARTESIAN_POINT('',(17.3433420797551,2.33910834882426,3.11404009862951));
#685=CARTESIAN_POINT('',(17.3291177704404,2.44130498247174,3.24833202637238));
#686=CARTESIAN_POINT('',(17.3026372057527,2.62244343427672,3.53321288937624));
#687=CARTESIAN_POINT('',(17.2903944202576,2.70122890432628,3.68390259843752));
#688=CARTESIAN_POINT('',(17.2694082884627,2.8323085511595,3.99662262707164));
#689=CARTESIAN_POINT('',(17.2606646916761,2.88460462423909,4.15865213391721));
#690=CARTESIAN_POINT('',(17.2477710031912,2.96072391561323,4.487783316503));
#691=CARTESIAN_POINT('',(17.243577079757,2.98481900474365,4.65482036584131));
#692=CARTESIAN_POINT('',(17.2401251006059,3.00469550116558,4.99061513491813));
#693=CARTESIAN_POINT('',(17.2408666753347,3.00047902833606,5.15937272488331));
#694=CARTESIAN_POINT('',(17.2471619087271,2.9640733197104,5.4918711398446));
#695=CARTESIAN_POINT('',(17.2526628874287,2.93219030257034,5.65564663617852));
#696=CARTESIAN_POINT('',(17.2677745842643,2.84183747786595,5.97548891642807));
#697=CARTESIAN_POINT('',(17.2773854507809,2.78336671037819,6.13155542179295));
#698=CARTESIAN_POINT('',(17.2996905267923,2.64119011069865,6.43246174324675));
#699=CARTESIAN_POINT('',(17.3124001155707,2.55735789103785,6.57724065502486));
#700=CARTESIAN_POINT('',(17.3394600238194,2.36692773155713,6.85079247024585));
#701=CARTESIAN_POINT('',(17.3538104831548,2.26032785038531,6.97956400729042));
#702=CARTESIAN_POINT('',(17.3827662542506,2.02572372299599,7.21921755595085));
#703=CARTESIAN_POINT('',(17.397372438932,1.89745691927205,7.32984259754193));
#704=CARTESIAN_POINT('',(17.425020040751,1.62404588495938,7.52803945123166));
#705=CARTESIAN_POINT('',(17.4380614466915,1.47890153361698,7.61561109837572));
#706=CARTESIAN_POINT('',(17.4611302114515,1.17560813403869,7.76524184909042));
#707=CARTESIAN_POINT('',(17.4711547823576,1.01744722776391,7.82727737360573));
#708=CARTESIAN_POINT('',(17.4870382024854,0.692740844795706,7.9238318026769));
#709=CARTESIAN_POINT('',(17.4928974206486,0.526196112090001,7.95835314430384));
#710=CARTESIAN_POINT('',(17.4997401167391,0.191663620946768,7.99854888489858));
#711=CARTESIAN_POINT('',(17.5007831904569,0.0237194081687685,8.00457589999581));
#712=CARTESIAN_POINT('',(17.4980396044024,-0.310778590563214,7.98855325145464));
#713=CARTESIAN_POINT('',(17.4942531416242,-0.477332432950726,7.96650473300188));
#714=CARTESIAN_POINT('',(17.4823128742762,-0.803226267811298,7.8952501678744));
#715=CARTESIAN_POINT('',(17.474187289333,-0.962605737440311,7.84621953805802));
#716=CARTESIAN_POINT('',(17.4544761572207,-1.27088253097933,7.72258016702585));
#717=CARTESIAN_POINT('',(17.4428904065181,-1.41977923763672,7.64796992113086));
#718=CARTESIAN_POINT('',(17.417396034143,-1.70438969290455,7.47448758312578));
#719=CARTESIAN_POINT('',(17.4034668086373,-1.83996793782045,7.37539627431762));
#720=CARTESIAN_POINT('',(17.374890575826,-2.09269752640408,7.15606511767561));
#721=CARTESIAN_POINT('',(17.3602435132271,-2.20984744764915,7.0358236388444));
#722=CARTESIAN_POINT('',(17.3316886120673,-2.42370922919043,6.77602051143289));
#723=CARTESIAN_POINT('',(17.3177906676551,-2.52018230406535,6.63626104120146));
#724=CARTESIAN_POINT('',(17.2924954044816,-2.68828177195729,6.34231277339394));
#725=CARTESIAN_POINT('',(17.2810980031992,-2.75990898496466,6.18812445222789));
#726=CARTESIAN_POINT('',(17.2621692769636,-2.87593039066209,5.8703495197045));
#727=CARTESIAN_POINT('',(17.2546213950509,-2.92044137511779,5.70680658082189));
#728=CARTESIAN_POINT('',(17.2442055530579,-2.98133287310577,5.37442453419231));
#729=CARTESIAN_POINT('',(17.2413371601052,-2.99771598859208,5.20558591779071));
#730=CARTESIAN_POINT('',(17.2406244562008,-3.00181092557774,4.8697911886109));
#731=CARTESIAN_POINT('',(17.2427142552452,-2.98989876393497,4.70283968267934));
#732=CARTESIAN_POINT('',(17.2515376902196,-2.93855658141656,4.37335448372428));
#733=CARTESIAN_POINT('',(17.2582713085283,-2.89912666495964,4.21082077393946));
#734=CARTESIAN_POINT('',(17.2755980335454,-2.79401555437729,3.89494278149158));
#735=CARTESIAN_POINT('',(17.2861861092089,-2.72836856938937,3.74158682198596));
#736=CARTESIAN_POINT('',(17.3100332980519,-2.57272591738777,3.44800444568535));
#737=CARTESIAN_POINT('',(17.323292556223,-2.48272892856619,3.3077787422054));
#738=CARTESIAN_POINT('',(17.3511960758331,-2.27960652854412,3.04254108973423));
#739=CARTESIAN_POINT('',(17.3658556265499,-2.1662051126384,2.91774208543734));
#740=CARTESIAN_POINT('',(17.3947877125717,-1.92007371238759,2.68881673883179));
#741=CARTESIAN_POINT('',(17.4090601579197,-1.78733928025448,2.58469516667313));
#742=CARTESIAN_POINT('',(17.4357318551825,-1.50514767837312,2.3993770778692));
#743=CARTESIAN_POINT('',(17.4481165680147,-1.35557476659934,2.31835468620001));
#744=CARTESIAN_POINT('',(17.4694759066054,-1.0447868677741,2.18271231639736));
#745=CARTESIAN_POINT('',(17.4784538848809,-0.88358351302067,2.1280663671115));
#746=CARTESIAN_POINT('',(17.4900568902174,-0.60148793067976,2.05842313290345));
#747=CARTESIAN_POINT('',(17.4937653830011,-0.48229049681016,2.03655005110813));
#748=CARTESIAN_POINT('',(17.4987379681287,-0.242077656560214,2.00733621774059));
#749=CARTESIAN_POINT('',(17.5000021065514,-0.121062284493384,1.99999519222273));
#750=CARTESIAN_POINT('',(17.5,0.,2.));
#751=B_SPLINE_CURVE_WITH_KNOTS('',3,(#673,#674,#675,#676,#677,#678,#679,#680,#681,#682,#683,
#684,#685,#686,#687,#688,#689,#690,#691,#692,#693,#694,#695,#696,#697,#698,#699,#700,#701,#702,
#703,#704,#705,#706,#707,#708,#709,#710,#711,#712,#713,#714,#715,#716,#717,#718,#719,#720,#721,
#722,#723,#724,#725,#726,#727,#728,#729,#730,#731,#732,#733,#734,#735,#736,#737,#738,#739,#740,
#741,#742,#743,#744,#745,#746,#747,#748,#749,#750),.UNSPECIFIED.,.T.,.F.,(4,2,2,2,2,2,2,2,2,2,2,
2,2,2,2,2,2,2,2,2,2,2,2,2,2,2,2,2,2,2,2,2,2,2,2,2,2,2,4),(0.,0.501151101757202,1.00275497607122,
1.50393968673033,2.00507078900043,2.51072843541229,3.01641891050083,3.52541434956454,
4.03437334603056,4.53838423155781,5.04235737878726,5.54082259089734,6.03930580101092,
6.54031528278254,7.04136750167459,7.54899572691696,8.05662758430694,8.56472712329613,
9.07278165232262,9.57453227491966,10.076262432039,10.5747686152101,11.0733041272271,
11.5764767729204,12.0796882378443,12.5884304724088,13.0971559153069,13.6036744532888,
14.1101461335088,14.6099250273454,15.1097020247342,15.6088290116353,16.1079830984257,
16.6133996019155,17.1189325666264,17.6281812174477,18.1369274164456,18.4998006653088,
18.8626670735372),.UNSPECIFIED.);
#752=CARTESIAN_POINT('',(17.5,0.,2.));
#753=VERTEX_POINT('',#752);
#754=EDGE_CURVE('E9',#753,#753,#751,.T.);
#755=ORIENTED_EDGE('',*,*,#754,.F.);
#756=EDGE_LOOP('',(#755));
#757=FACE_BOUND('',#756,.T.);
#758=ORIENTED_EDGE('',*,*,#660,.T.);
#759=EDGE_LOOP('',(#758));
#760=FACE_BOUND('',#759,.T.);
#761=CARTESIAN_POINT('',(0.,0.,0.2));
#762=DIRECTION('',(0.,0.,-1.));
#763=DIRECTION('',(0.,-1.,0.));
#764=AXIS2_PLACEMENT_3D('',#761,#762,#763);
#765=CIRCLE('',#764,17.5);
#766=CARTESIAN_POINT('',(0.,-17.5,0.2));
#767=VERTEX_POINT('',#766);
#768=EDGE_CURVE('E709',#767,#767,#765,.F.);
#769=ORIENTED_EDGE('',*,*,#768,.T.);
#770=EDGE_LOOP('',(#769));
#771=FACE_BOUND('',#770,.T.);
#772=ADVANCED_FACE('F186',(#757,#760,#771),#672,.T.);
#773=CARTESIAN_POINT('',(-15.25,0.,0.2));
#774=DIRECTION('',(0.,0.,-1.));
#775=DIRECTION('',(-1.,0.,0.));
#776=AXIS2_PLACEMENT_3D('',#773,#774,#775);
#777=PLANE('',#776);
#778=CARTESIAN_POINT('',(0.,0.,0.2));
#779=DIRECTION('',(0.,0.,-1.));
#780=DIRECTION('',(0.,-1.,0.));
#781=AXIS2_PLACEMENT_3D('',#778,#779,#780);
#782=CIRCLE('',#781,13.);
#783=CARTESIAN_POINT('',(0.,-13.,0.2));
#784=VERTEX_POINT('',#783);
#785=EDGE_CURVE('E706',#784,#784,#782,.F.);
#786=ORIENTED_EDGE('',*,*,#785,.T.);
#787=EDGE_LOOP('',(#786));
#788=FACE_BOUND('',#787,.T.);
#789=ORIENTED_EDGE('',*,*,#768,.F.);
#790=EDGE_LOOP('',(#789));
#791=FACE_BOUND('',#790,.T.);
#792=ADVANCED_FACE('F191',(#788,#791),#777,.T.);
#793=CARTESIAN_POINT('',(0.,0.,0.1));
#794=DIRECTION('',(0.,0.,-1.));
#795=DIRECTION('',(0.,-1.,0.));
#796=AXIS2_PLACEMENT_3D('',#793,#794,#795);
#797=CYLINDRICAL_SURFACE('',#796,13.);
#798=ORIENTED_EDGE('',*,*,#785,.F.);
#799=EDGE_LOOP('',(#798));
#800=FACE_BOUND('',#799,.T.);
#801=CARTESIAN_POINT('',(0.,0.,0.));
#802=DIRECTION('',(0.,0.,-1.));
#803=DIRECTION('',(0.,-1.,0.));
#804=AXIS2_PLACEMENT_3D('',#801,#802,#803);
#805=CIRCLE('',#804,13.);
#806=CARTESIAN_POINT('',(0.,-13.,0.));
#807=VERTEX_POINT('',#806);
#808=EDGE_CURVE('E713',#807,#807,#805,.F.);
#809=ORIENTED_EDGE('',*,*,#808,.T.);
#810=EDGE_LOOP('',(#809));
#811=FACE_BOUND('',#810,.T.);
#812=ADVANCED_FACE('F686',(#800,#811),#797,.T.);
#813=CARTESIAN_POINT('',(-9.7,0.,0.));
#814=DIRECTION('',(0.,0.,-1.));
#815=DIRECTION('',(0.,-1.,0.));
#816=AXIS2_PLACEMENT_3D('',#813,#814,#815);
#817=PLANE('',#816);
#818=CARTESIAN_POINT('',(0.,0.,0.));
#819=DIRECTION('',(0.,0.,-1.));
#820=DIRECTION('',(0.,-1.,0.));
#821=AXIS2_PLACEMENT_3D('',#818,#819,#820);
#822=CIRCLE('',#821,6.39999999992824);
#823=CARTESIAN_POINT('',(0.,-6.39999999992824,0.));
#824=VERTEX_POINT('',#823);
#825=EDGE_CURVE('E721',#824,#824,#822,.F.);
#826=ORIENTED_EDGE('',*,*,#825,.T.);
#827=EDGE_LOOP('',(#826));
#828=FACE_BOUND('',#827,.T.);
#829=ORIENTED_EDGE('',*,*,#808,.F.);
#830=EDGE_LOOP('',(#829));
#831=FACE_BOUND('',#830,.T.);
#832=ADVANCED_FACE('F691',(#828,#831),#817,.T.);
#833=CARTESIAN_POINT('',(0.,0.,5.6843418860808E-11));
#834=DIRECTION('',(0.,0.,-1.));
#835=DIRECTION('',(0.,-1.,0.));
#836=AXIS2_PLACEMENT_3D('',#833,#834,#835);
#837=CONICAL_SURFACE('',#836,6.3999999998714,0.785398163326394);
#838=ORIENTED_EDGE('',*,*,#825,.F.);
#839=EDGE_LOOP('',(#838));
#840=FACE_BOUND('',#839,.T.);
#841=CARTESIAN_POINT('',(0.,0.,0.399999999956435));
#842=DIRECTION('',(0.,0.,-1.));
#843=DIRECTION('',(-1.,0.,0.));
#844=AXIS2_PLACEMENT_3D('',#841,#842,#843);
#845=CIRCLE('',#844,5.99999999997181);
#846=CARTESIAN_POINT('',(-5.99999999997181,0.,0.399999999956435));
#847=VERTEX_POINT('',#846);
#848=EDGE_CURVE('E724',#847,#847,#845,.T.);
#849=ORIENTED_EDGE('',*,*,#848,.F.);
#850=EDGE_LOOP('',(#849));
#851=FACE_BOUND('',#850,.T.);
#852=ADVANCED_FACE('F788',(#840,#851),#837,.F.);
#853=CARTESIAN_POINT('',(0.,0.,13.5));
#854=DIRECTION('',(0.,0.,-1.));
#855=DIRECTION('',(0.,-1.,0.));
#856=AXIS2_PLACEMENT_3D('',#853,#854,#855);
#857=CYLINDRICAL_SURFACE('',#856,6.);
#858=CARTESIAN_POINT('',(6.,0.,2.5));
#859=CARTESIAN_POINT('',(5.99999628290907,0.133903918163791,2.5000047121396));
#860=CARTESIAN_POINT('',(5.99546656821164,0.268039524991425,2.51082131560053));
#861=CARTESIAN_POINT('',(5.97780115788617,0.532498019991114,2.55368073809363));
#862=CARTESIAN_POINT('',(5.96464300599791,0.66281002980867,2.58577894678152));
#863=CARTESIAN_POINT('',(5.93112629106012,0.915376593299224,2.6698214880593));
#864=CARTESIAN_POINT('',(5.91079213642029,1.03765681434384,2.72169859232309));
#865=CARTESIAN_POINT('',(5.8649055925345,1.27165974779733,2.84354583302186));
#866=CARTESIAN_POINT('',(5.83935478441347,1.38338564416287,2.91351048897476));
#867=CARTESIAN_POINT('',(5.78415660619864,1.59889674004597,3.07325791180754));
#868=CARTESIAN_POINT('',(5.75437507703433,1.70208251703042,3.1638026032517));
#869=CARTESIAN_POINT('',(5.69465427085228,1.8923196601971,3.36052868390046));
#870=CARTESIAN_POINT('',(5.66471491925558,1.9793625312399,3.46671825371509));
#871=CARTESIAN_POINT('',(5.60642043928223,2.13907474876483,3.69805355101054));
#872=CARTESIAN_POINT('',(5.57821573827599,2.2108261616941,3.82387489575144));
#873=CARTESIAN_POINT('',(5.52871144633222,2.331878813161,4.08714651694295));
#874=CARTESIAN_POINT('',(5.50740829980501,2.38119161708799,4.22459075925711));
#875=CARTESIAN_POINT('',(5.47557110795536,2.45349196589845,4.50030738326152));
#876=CARTESIAN_POINT('',(5.46456775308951,2.47763315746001,4.63822096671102));
#877=CARTESIAN_POINT('',(5.45322652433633,2.50250419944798,4.91654658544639));
#878=CARTESIAN_POINT('',(5.45288276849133,2.5032469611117,5.05695720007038));
#879=CARTESIAN_POINT('',(5.46250239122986,2.48216900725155,5.32480012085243));
#880=CARTESIAN_POINT('',(5.47167765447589,2.46207362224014,5.45240219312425));
#881=CARTESIAN_POINT('',(5.49796965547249,2.40278382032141,5.70222418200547));
#882=CARTESIAN_POINT('',(5.51508791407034,2.36358574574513,5.82444306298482));
#883=CARTESIAN_POINT('',(5.55572369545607,2.2664391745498,6.06311540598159));
#884=CARTESIAN_POINT('',(5.57936963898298,2.20810943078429,6.17939084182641));
#885=CARTESIAN_POINT('',(5.63036662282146,2.07462485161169,6.40095546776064));
#886=CARTESIAN_POINT('',(5.65771912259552,1.99946338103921,6.50624030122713));
#887=CARTESIAN_POINT('',(5.71585953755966,1.82699193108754,6.71219991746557));
#888=CARTESIAN_POINT('',(5.74674242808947,1.72834696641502,6.81173313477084));
#889=CARTESIAN_POINT('',(5.80651346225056,1.51545918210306,6.99322700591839));
#890=CARTESIAN_POINT('',(5.83540113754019,1.40121271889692,7.07518354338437));
#891=CARTESIAN_POINT('',(5.88876567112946,1.15689589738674,7.22087164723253));
#892=CARTESIAN_POINT('',(5.91312533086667,1.02652116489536,7.28413889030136));
#893=CARTESIAN_POINT('',(5.95378962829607,0.755704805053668,7.38744227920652));
#894=CARTESIAN_POINT('',(5.970098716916,0.615268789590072,7.42749126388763));
#895=CARTESIAN_POINT('',(5.9919928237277,0.337856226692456,7.48083198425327));
#896=CARTESIAN_POINT('',(5.9981908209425,0.201222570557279,7.4956557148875));
#897=CARTESIAN_POINT('',(6.00112100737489,-0.0727093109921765,7.50269244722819));
#898=CARTESIAN_POINT('',(5.99785591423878,-0.210007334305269,7.494911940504));
#899=CARTESIAN_POINT('',(5.9826243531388,-0.47419648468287,7.45805783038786));
#900=CARTESIAN_POINT('',(5.97109774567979,-0.601265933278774,7.43006009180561));
#901=CARTESIAN_POINT('',(5.94097213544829,-0.848765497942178,7.35506361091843));
#902=CARTESIAN_POINT('',(5.92237223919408,-0.969194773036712,7.30806246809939));
#903=CARTESIAN_POINT('',(5.87916541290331,-1.20421799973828,7.19485804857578));
#904=CARTESIAN_POINT('',(5.85438982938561,-1.31851447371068,7.12810363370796));
#905=CARTESIAN_POINT('',(5.80147609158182,-1.53469243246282,6.97789324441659));
#906=CARTESIAN_POINT('',(5.77333653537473,-1.63656870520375,6.89443029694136));
#907=CARTESIAN_POINT('',(5.71424175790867,-1.83266686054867,6.7061935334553));
#908=CARTESIAN_POINT('',(5.68322903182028,-1.92582139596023,6.6003229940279));
#909=CARTESIAN_POINT('',(5.6236867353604,-2.09333969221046,6.3739574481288));
#910=CARTESIAN_POINT('',(5.59515772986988,-2.16769918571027,6.25345912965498));
#911=CARTESIAN_POINT('',(5.54362772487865,-2.29631920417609,5.99877164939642));
#912=CARTESIAN_POINT('',(5.52071125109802,-2.35027836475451,5.86441192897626));
#913=CARTESIAN_POINT('',(5.48416711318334,-2.43434827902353,5.58725881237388));
#914=CARTESIAN_POINT('',(5.47053179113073,-2.46447869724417,5.44447247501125));
#915=CARTESIAN_POINT('',(5.4552632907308,-2.49808160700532,5.16636260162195));
#916=CARTESIAN_POINT('',(5.45278701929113,-2.50342760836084,5.03131067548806));
#917=CARTESIAN_POINT('',(5.45787706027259,-2.49231151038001,4.76231427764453));
#918=CARTESIAN_POINT('',(5.46544183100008,-2.47585275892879,4.6283696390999));
#919=CARTESIAN_POINT('',(5.48899102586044,-2.42316809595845,4.37181450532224));
#920=CARTESIAN_POINT('',(5.50456709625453,-2.38789807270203,4.24896665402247));
#921=CARTESIAN_POINT('',(5.54206362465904,-2.29952656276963,4.01090395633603));
#922=CARTESIAN_POINT('',(5.56398586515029,-2.24642006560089,3.89569126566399));
#923=CARTESIAN_POINT('',(5.61333908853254,-2.1202057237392,3.66860821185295));
#924=CARTESIAN_POINT('',(5.64102204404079,-2.04608723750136,3.55735535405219));
#925=CARTESIAN_POINT('',(5.69807379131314,-1.88136812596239,3.34827970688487));
#926=CARTESIAN_POINT('',(5.72744316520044,-1.79076178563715,3.25046159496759));
#927=CARTESIAN_POINT('',(5.78712781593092,-1.58780416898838,3.06370269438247));
#928=CARTESIAN_POINT('',(5.81735619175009,-1.47434977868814,2.9759273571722));
#929=CARTESIAN_POINT('',(5.87320303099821,-1.23319985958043,2.82060086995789));
#930=CARTESIAN_POINT('',(5.89881939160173,-1.1054978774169,2.75305893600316));
#931=CARTESIAN_POINT('',(5.94218308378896,-0.841465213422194,2.6415811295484));
#932=CARTESIAN_POINT('',(5.96005349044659,-0.705312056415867,2.59727350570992));
#933=CARTESIAN_POINT('',(5.9864223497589,-0.426816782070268,2.53258431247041));
#934=CARTESIAN_POINT('',(5.99495014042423,-0.28449550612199,2.51212783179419));
#935=CARTESIAN_POINT('',(5.99888566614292,-0.118052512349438,2.50267615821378));
#936=CARTESIAN_POINT('',(5.99930292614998,-0.0944569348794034,2.50167339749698));
#937=CARTESIAN_POINT('',(5.99986042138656,-0.0472433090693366,2.50033490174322));
#938=CARTESIAN_POINT('',(6.0000006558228,-0.0236252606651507,2.49999916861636));
#939=CARTESIAN_POINT('',(6.,0.,2.5));
#940=B_SPLINE_CURVE_WITH_KNOTS('',3,(#858,#859,#860,#861,#862,#863,#864,#865,#866,#867,#868,
#869,#870,#871,#872,#873,#874,#875,#876,#877,#878,#879,#880,#881,#882,#883,#884,#885,#886,#887,
#888,#889,#890,#891,#892,#893,#894,#895,#896,#897,#898,#899,#900,#901,#902,#903,#904,#905,#906,
#907,#908,#909,#910,#911,#912,#913,#914,#915,#916,#917,#918,#919,#920,#921,#922,#923,#924,#925,
#926,#927,#928,#929,#930,#931,#932,#933,#934,#935,#936,#937,#938,#939),.UNSPECIFIED.,.T.,.F.,(4,
2,2,2,2,2,2,2,2,2,2,2,2,2,2,2,2,2,2,2,2,2,2,2,2,2,2,2,2,2,2,2,2,2,2,2,2,2,2,2,4),(0.,
0.401613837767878,0.804277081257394,1.2055837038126,1.60676887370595,2.02635872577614,
2.44616876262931,2.88663449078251,3.32687293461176,3.74590546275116,4.16470676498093,
4.55140314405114,4.93817359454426,5.33317426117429,5.72833091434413,6.15688282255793,
6.58553498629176,7.02408110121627,7.46238448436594,7.87296886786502,8.28343534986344,
8.67353179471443,9.0636775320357,9.46594270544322,9.86837610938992,10.2995697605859,
10.7308612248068,11.1682957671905,11.6053689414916,12.0087975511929,12.4121642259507,
12.7967529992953,13.1814498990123,13.5892778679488,13.9972474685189,14.4349307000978,
14.8728129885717,15.3034571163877,15.7327450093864,15.8036033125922,15.8744618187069),.UNSPECIFIED.);
#941=CARTESIAN_POINT('',(6.,0.,2.5));
#942=VERTEX_POINT('',#941);
#943=EDGE_CURVE('E200',#942,#942,#940,.T.);
#944=ORIENTED_EDGE('',*,*,#943,.T.);
#945=EDGE_LOOP('',(#944));
#946=FACE_BOUND('',#945,.T.);
#947=CARTESIAN_POINT('',(0.,0.,26.6));
#948=DIRECTION('',(0.,0.,-1.));
#949=DIRECTION('',(0.,-1.,0.));
#950=AXIS2_PLACEMENT_3D('',#947,#948,#949);
#951=CIRCLE('',#950,6.);
#952=CARTESIAN_POINT('',(0.,-6.,26.6));
#953=VERTEX_POINT('',#952);
#954=EDGE_CURVE('E728',#953,#953,#951,.T.);
#955=ORIENTED_EDGE('',*,*,#954,.F.);
#956=EDGE_LOOP('',(#955));
#957=FACE_BOUND('',#956,.T.);
#958=ORIENTED_EDGE('',*,*,#848,.T.);
#959=EDGE_LOOP('',(#958));
#960=FACE_BOUND('',#959,.T.);
#961=ADVANCED_FACE('F774',(#946,#957,#960),#857,.F.);
#962=CARTESIAN_POINT('',(0.,0.,26.9999999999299));
#963=DIRECTION('',(0.,0.,1.));
#964=DIRECTION('',(0.,1.,0.));
#965=AXIS2_PLACEMENT_3D('',#962,#963,#964);
#966=CONICAL_SURFACE('',#965,6.3999999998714,0.785398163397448);
#967=ORIENTED_EDGE('',*,*,#954,.T.);
#968=EDGE_LOOP('',(#967));
#969=FACE_BOUND('',#968,.T.);
#970=CARTESIAN_POINT('',(0.,0.,27.0000000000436));
#971=DIRECTION('',(0.,0.,1.));
#972=DIRECTION('',(0.,1.,0.));
#973=AXIS2_PLACEMENT_3D('',#970,#971,#972);
#974=CIRCLE('',#973,6.39999999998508);
#975=CARTESIAN_POINT('',(0.,6.39999999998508,27.0000000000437));
#976=VERTEX_POINT('',#975);
#977=EDGE_CURVE('E725',#976,#976,#974,.F.);
#978=ORIENTED_EDGE('',*,*,#977,.F.);
#979=EDGE_LOOP('',(#978));
#980=FACE_BOUND('',#979,.T.);
#981=ADVANCED_FACE('F805',(#969,#980),#966,.F.);
#982=CARTESIAN_POINT('',(-9.2,0.,27.));
#983=DIRECTION('',(0.,0.,1.));
#984=DIRECTION('',(0.,1.,0.));
#985=AXIS2_PLACEMENT_3D('',#982,#983,#984);
#986=PLANE('',#985);
#987=CARTESIAN_POINT('',(0.,0.,27.));
#988=DIRECTION('',(0.,0.,-1.));
#989=DIRECTION('',(0.,-1.,0.));
#990=AXIS2_PLACEMENT_3D('',#987,#988,#989);
#991=CIRCLE('',#990,12.);
#992=CARTESIAN_POINT('',(0.,-12.,27.));
#993=VERTEX_POINT('',#992);
#994=EDGE_CURVE('E729',#993,#993,#991,.F.);
#995=ORIENTED_EDGE('',*,*,#994,.T.);
#996=EDGE_LOOP('',(#995));
#997=FACE_BOUND('',#996,.T.);
#998=ORIENTED_EDGE('',*,*,#977,.T.);
#999=EDGE_LOOP('',(#998));
#1000=FACE_BOUND('',#999,.T.);
#1001=ADVANCED_FACE('F810',(#997,#1000),#986,.T.);
#1002=CARTESIAN_POINT('',(0.,0.,28.35));
#1003=DIRECTION('',(0.,0.,-1.));
#1004=DIRECTION('',(0.,-1.,0.));
#1005=AXIS2_PLACEMENT_3D('',#1002,#1003,#1004);
#1006=CYLINDRICAL_SURFACE('',#1005,12.);
#1007=ORIENTED_EDGE('',*,*,#994,.F.);
#1008=EDGE_LOOP('',(#1007));
#1009=FACE_BOUND('',#1008,.T.);
#1010=CARTESIAN_POINT('',(0.,0.,29.7));
#1011=DIRECTION('',(0.,0.,-1.));
#1012=DIRECTION('',(0.,-1.,0.));
#1013=AXIS2_PLACEMENT_3D('',#1010,#1011,#1012);
#1014=CIRCLE('',#1013,12.);
#1015=CARTESIAN_POINT('',(0.,-12.,29.7));
#1016=VERTEX_POINT('',#1015);
#1017=EDGE_CURVE('E732',#1016,#1016,#1014,.T.);
#1018=ORIENTED_EDGE('',*,*,#1017,.F.);
#1019=EDGE_LOOP('',(#1018));
#1020=FACE_BOUND('',#1019,.T.);
#1021=ADVANCED_FACE('F820',(#1009,#1020),#1006,.F.);
#1022=CARTESIAN_POINT('',(-6.,0.,29.7));
#1023=DIRECTION('',(0.,0.,-1.));
#1024=DIRECTION('',(0.,-1.,0.));
#1025=AXIS2_PLACEMENT_3D('',#1022,#1023,#1024);
#1026=PLANE('',#1025);
#1027=ORIENTED_EDGE('',*,*,#1017,.T.);
#1028=EDGE_LOOP('',(#1027));
#1029=FACE_BOUND('',#1028,.T.);
#1030=ADVANCED_FACE('F17',(#1029),#1026,.T.);
#1031=CARTESIAN_POINT('',(49.,-1.19325,29.));
#1032=DIRECTION('',(0.,0.,-1.));
#1033=DIRECTION('',(0.,-1.,0.));
#1034=AXIS2_PLACEMENT_3D('',#1031,#1032,#1033);
#1035=PLANE('',#1034);
#1036=CARTESIAN_POINT('',(49.,0.,29.0000000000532));
#1037=DIRECTION('',(0.,0.,1.));
#1038=DIRECTION('',(1.,0.,0.));
#1039=AXIS2_PLACEMENT_3D('',#1036,#1037,#1038);
#1040=CIRCLE('',#1039,2.3865000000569);
#1041=CARTESIAN_POINT('',(51.3865000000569,0.,29.0000000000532));
#1042=VERTEX_POINT('',#1041);
#1043=EDGE_CURVE('E250',#1042,#1042,#1040,.T.);
#1044=ORIENTED_EDGE('',*,*,#1043,.F.);
#1045=EDGE_LOOP('',(#1044));
#1046=FACE_BOUND('',#1045,.T.);
#1047=DIRECTION('',(0.,-1.,0.));
#1048=VECTOR('',#1047,1.);
#1049=CARTESIAN_POINT('',(47.5,-0.866025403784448,29.));
#1050=LINE('',#1049,#1048);
#1051=CARTESIAN_POINT('',(47.5,0.86602540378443,29.));
#1052=VERTEX_POINT('',#1051);
#1053=CARTESIAN_POINT('',(47.5,-0.866025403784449,29.));
#1054=VERTEX_POINT('',#1053);
#1055=EDGE_CURVE('E275',#1052,#1054,#1050,.T.);
#1056=ORIENTED_EDGE('',*,*,#1055,.T.);
#1057=DIRECTION('',(0.866025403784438,-0.5,0.));
#1058=VECTOR('',#1057,1.);
#1059=CARTESIAN_POINT('',(47.5,-0.866025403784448,29.));
#1060=LINE('',#1059,#1058);
#1061=CARTESIAN_POINT('',(49.,-1.73205080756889,29.));
#1062=VERTEX_POINT('',#1061);
#1063=EDGE_CURVE('E251',#1054,#1062,#1060,.T.);
#1064=ORIENTED_EDGE('',*,*,#1063,.T.);
#1065=DIRECTION('',(0.866025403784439,0.5,0.));
#1066=VECTOR('',#1065,1.);
#1067=CARTESIAN_POINT('',(50.5,-0.866025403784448,29.));
#1068=LINE('',#1067,#1066);
#1069=CARTESIAN_POINT('',(50.5,-0.866025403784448,29.));
#1070=VERTEX_POINT('',#1069);
#1071=EDGE_CURVE('E272',#1062,#1070,#1068,.T.);
#1072=ORIENTED_EDGE('',*,*,#1071,.T.);
#1073=DIRECTION('',(0.,1.,0.));
#1074=VECTOR('',#1073,1.);
#1075=CARTESIAN_POINT('',(50.5,0.86602540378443,29.));
#1076=LINE('',#1075,#1074);
#1077=CARTESIAN_POINT('',(50.5,0.866025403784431,29.));
#1078=VERTEX_POINT('',#1077);
#1079=EDGE_CURVE('E286',#1070,#1078,#1076,.T.);
#1080=ORIENTED_EDGE('',*,*,#1079,.T.);
#1081=DIRECTION('',(-0.866025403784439,0.5,0.));
#1082=VECTOR('',#1081,1.);
#1083=CARTESIAN_POINT('',(49.,1.73205080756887,29.));
#1084=LINE('',#1083,#1082);
#1085=CARTESIAN_POINT('',(49.,1.73205080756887,29.));
#1086=VERTEX_POINT('',#1085);
#1087=EDGE_CURVE('E301',#1078,#1086,#1084,.T.);
#1088=ORIENTED_EDGE('',*,*,#1087,.T.);
#1089=DIRECTION('',(-0.866025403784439,-0.5,0.));
#1090=VECTOR('',#1089,1.);
#1091=CARTESIAN_POINT('',(47.5,0.86602540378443,29.));
#1092=LINE('',#1091,#1090);
#1093=EDGE_CURVE('E292',#1086,#1052,#1092,.T.);
#1094=ORIENTED_EDGE('',*,*,#1093,.T.);
#1095=EDGE_LOOP('',(#1056,#1064,#1072,#1080,#1088,#1094));
#1096=FACE_BOUND('',#1095,.T.);
#1097=ADVANCED_FACE('F405',(#1046,#1096),#1035,.T.);
#1098=CARTESIAN_POINT('',(49.,-1.73205080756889,29.));
#1099=DIRECTION('',(-0.5,-0.866025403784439,0.));
#1100=DIRECTION('',(0.866025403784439,-0.5,0.));
#1101=AXIS2_PLACEMENT_3D('',#1098,#1099,#1100);
#1102=PLANE('',#1101);
#1103=DIRECTION('',(0.,0.,1.));
#1104=VECTOR('',#1103,1.);
#1105=CARTESIAN_POINT('',(49.,-1.73205080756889,29.));
#1106=LINE('',#1105,#1104);
#1107=CARTESIAN_POINT('',(49.,-1.73205080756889,32.));
#1108=VERTEX_POINT('',#1107);
#1109=EDGE_CURVE('E257',#1062,#1108,#1106,.T.);
#1110=ORIENTED_EDGE('',*,*,#1109,.F.);
#1111=ORIENTED_EDGE('',*,*,#1063,.F.);
#1112=DIRECTION('',(0.,0.,1.));
#1113=VECTOR('',#1112,1.);
#1114=CARTESIAN_POINT('',(47.5,-0.866025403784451,29.));
#1115=LINE('',#1114,#1113);
#1116=CARTESIAN_POINT('',(47.5,-0.866025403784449,32.));
#1117=VERTEX_POINT('',#1116);
#1118=EDGE_CURVE('E260',#1117,#1054,#1115,.F.);
#1119=ORIENTED_EDGE('',*,*,#1118,.F.);
#1120=DIRECTION('',(0.866025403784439,-0.5,0.));
#1121=VECTOR('',#1120,1.);
#1122=CARTESIAN_POINT('',(49.,-1.73205080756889,32.));
#1123=LINE('',#1122,#1121);
#1124=EDGE_CURVE('E254',#1108,#1117,#1123,.F.);
#1125=ORIENTED_EDGE('',*,*,#1124,.F.);
#1126=EDGE_LOOP('',(#1110,#1111,#1119,#1125));
#1127=FACE_BOUND('',#1126,.T.);
#1128=ADVANCED_FACE('F408',(#1127),#1102,.F.);
#1129=CARTESIAN_POINT('',(49.,0.,32.));
#1130=DIRECTION('',(0.,0.,1.));
#1131=DIRECTION('',(0.,1.,0.));
#1132=AXIS2_PLACEMENT_3D('',#1129,#1130,#1131);
#1133=PLANE('',#1132);
#1134=ORIENTED_EDGE('',*,*,#1124,.T.);
#1135=DIRECTION('',(0.,1.,0.));
#1136=VECTOR('',#1135,1.);
#1137=CARTESIAN_POINT('',(47.5,0.,32.));
#1138=LINE('',#1137,#1136);
#1139=CARTESIAN_POINT('',(47.5,0.86602540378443,32.));
#1140=VERTEX_POINT('',#1139);
#1141=EDGE_CURVE('E266',#1140,#1117,#1138,.F.);
#1142=ORIENTED_EDGE('',*,*,#1141,.F.);
#1143=DIRECTION('',(-0.866025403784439,-0.5,0.));
#1144=VECTOR('',#1143,1.);
#1145=CARTESIAN_POINT('',(47.5,0.86602540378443,32.));
#1146=LINE('',#1145,#1144);
#1147=CARTESIAN_POINT('',(49.,1.73205080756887,32.));
#1148=VERTEX_POINT('',#1147);
#1149=EDGE_CURVE('E289',#1140,#1148,#1146,.F.);
#1150=ORIENTED_EDGE('',*,*,#1149,.T.);
#1151=DIRECTION('',(-0.866025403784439,0.5,0.));
#1152=VECTOR('',#1151,1.);
#1153=CARTESIAN_POINT('',(49.,1.73205080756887,32.));
#1154=LINE('',#1153,#1152);
#1155=CARTESIAN_POINT('',(50.5,0.866025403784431,32.));
#1156=VERTEX_POINT('',#1155);
#1157=EDGE_CURVE('E298',#1148,#1156,#1154,.F.);
#1158=ORIENTED_EDGE('',*,*,#1157,.T.);
#1159=DIRECTION('',(0.,1.,0.));
#1160=VECTOR('',#1159,1.);
#1161=CARTESIAN_POINT('',(50.5,0.86602540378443,32.));
#1162=LINE('',#1161,#1160);
#1163=CARTESIAN_POINT('',(50.5,-0.866025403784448,32.));
#1164=VERTEX_POINT('',#1163);
#1165=EDGE_CURVE('E280',#1156,#1164,#1162,.F.);
#1166=ORIENTED_EDGE('',*,*,#1165,.T.);
#1167=DIRECTION('',(0.866025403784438,0.5,0.));
#1168=VECTOR('',#1167,1.);
#1169=CARTESIAN_POINT('',(49.,-1.73205080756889,32.));
#1170=LINE('',#1169,#1168);
#1171=EDGE_CURVE('E263',#1108,#1164,#1170,.T.);
#1172=ORIENTED_EDGE('',*,*,#1171,.F.);
#1173=EDGE_LOOP('',(#1134,#1142,#1150,#1158,#1166,#1172));
#1174=FACE_BOUND('',#1173,.T.);
#1175=ADVANCED_FACE('F412',(#1174),#1133,.F.);
#1176=CARTESIAN_POINT('',(50.5,-0.866025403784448,29.));
#1177=DIRECTION('',(0.5,-0.866025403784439,0.));
#1178=DIRECTION('',(0.866025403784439,0.5,0.));
#1179=AXIS2_PLACEMENT_3D('',#1176,#1177,#1178);
#1180=PLANE('',#1179);
#1181=DIRECTION('',(0.,0.,1.));
#1182=VECTOR('',#1181,1.);
#1183=CARTESIAN_POINT('',(50.5,-0.866025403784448,29.));
#1184=LINE('',#1183,#1182);
#1185=EDGE_CURVE('E269',#1070,#1164,#1184,.T.);
#1186=ORIENTED_EDGE('',*,*,#1185,.F.);
#1187=ORIENTED_EDGE('',*,*,#1071,.F.);
#1188=ORIENTED_EDGE('',*,*,#1109,.T.);
#1189=ORIENTED_EDGE('',*,*,#1171,.T.);
#1190=EDGE_LOOP('',(#1186,#1187,#1188,#1189));
#1191=FACE_BOUND('',#1190,.T.);
#1192=ADVANCED_FACE('F416',(#1191),#1180,.F.);
#1193=CARTESIAN_POINT('',(47.5,-0.866025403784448,29.));
#1194=DIRECTION('',(-1.,0.,0.));
#1195=DIRECTION('',(0.,-1.,0.));
#1196=AXIS2_PLACEMENT_3D('',#1193,#1194,#1195);
#1197=PLANE('',#1196);
#1198=ORIENTED_EDGE('',*,*,#1118,.T.);
#1199=ORIENTED_EDGE('',*,*,#1055,.F.);
#1200=DIRECTION('',(0.,0.,1.));
#1201=VECTOR('',#1200,1.);
#1202=CARTESIAN_POINT('',(47.5,0.86602540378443,29.));
#1203=LINE('',#1202,#1201);
#1204=EDGE_CURVE('E277',#1140,#1052,#1203,.F.);
#1205=ORIENTED_EDGE('',*,*,#1204,.F.);
#1206=ORIENTED_EDGE('',*,*,#1141,.T.);
#1207=EDGE_LOOP('',(#1198,#1199,#1205,#1206));
#1208=FACE_BOUND('',#1207,.T.);
#1209=ADVANCED_FACE('F420',(#1208),#1197,.F.);
#1210=CARTESIAN_POINT('',(50.5,0.86602540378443,29.));
#1211=DIRECTION('',(1.,0.,0.));
#1212=DIRECTION('',(0.,1.,0.));
#1213=AXIS2_PLACEMENT_3D('',#1210,#1211,#1212);
#1214=PLANE('',#1213);
#1215=DIRECTION('',(0.,0.,1.));
#1216=VECTOR('',#1215,1.);
#1217=CARTESIAN_POINT('',(50.5,0.86602540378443,29.));
#1218=LINE('',#1217,#1216);
#1219=EDGE_CURVE('E283',#1078,#1156,#1218,.T.);
#1220=ORIENTED_EDGE('',*,*,#1219,.F.);
#1221=ORIENTED_EDGE('',*,*,#1079,.F.);
#1222=ORIENTED_EDGE('',*,*,#1185,.T.);
#1223=ORIENTED_EDGE('',*,*,#1165,.F.);
#1224=EDGE_LOOP('',(#1220,#1221,#1222,#1223));
#1225=FACE_BOUND('',#1224,.T.);
#1226=ADVANCED_FACE('F424',(#1225),#1214,.F.);
#1227=CARTESIAN_POINT('',(47.5,0.86602540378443,29.));
#1228=DIRECTION('',(-0.5,0.866025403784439,0.));
#1229=DIRECTION('',(-0.866025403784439,-0.5,0.));
#1230=AXIS2_PLACEMENT_3D('',#1227,#1228,#1229);
#1231=PLANE('',#1230);
#1232=ORIENTED_EDGE('',*,*,#1204,.T.);
#1233=ORIENTED_EDGE('',*,*,#1093,.F.);
#1234=DIRECTION('',(0.,0.,1.));
#1235=VECTOR('',#1234,1.);
#1236=CARTESIAN_POINT('',(49.,1.73205080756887,29.));
#1237=LINE('',#1236,#1235);
#1238=EDGE_CURVE('E295',#1148,#1086,#1237,.F.);
#1239=ORIENTED_EDGE('',*,*,#1238,.F.);
#1240=ORIENTED_EDGE('',*,*,#1149,.F.);
#1241=EDGE_LOOP('',(#1232,#1233,#1239,#1240));
#1242=FACE_BOUND('',#1241,.T.);
#1243=ADVANCED_FACE('F427',(#1242),#1231,.F.);
#1244=CARTESIAN_POINT('',(49.,1.73205080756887,29.));
#1245=DIRECTION('',(0.5,0.866025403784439,0.));
#1246=DIRECTION('',(-0.866025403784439,0.5,0.));
#1247=AXIS2_PLACEMENT_3D('',#1244,#1245,#1246);
#1248=PLANE('',#1247);
#1249=ORIENTED_EDGE('',*,*,#1238,.T.);
#1250=ORIENTED_EDGE('',*,*,#1087,.F.);
#1251=ORIENTED_EDGE('',*,*,#1219,.T.);
#1252=ORIENTED_EDGE('',*,*,#1157,.F.);
#1253=EDGE_LOOP('',(#1249,#1250,#1251,#1252));
#1254=FACE_BOUND('',#1253,.T.);
#1255=ADVANCED_FACE('F213',(#1254),#1248,.F.);
#1256=CARTESIAN_POINT('',(49.,0.,29.6134999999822));
#1257=DIRECTION('',(0.,0.,1.));
#1258=DIRECTION('',(1.,0.,0.));
#1259=AXIS2_PLACEMENT_3D('',#1256,#1257,#1258);
#1260=CONICAL_SURFACE('',#1259,2.99999999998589,0.785398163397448);
#1261=ORIENTED_EDGE('',*,*,#1043,.T.);
#1262=EDGE_LOOP('',(#1261));
#1263=FACE_BOUND('',#1262,.T.);
#1264=ORIENTED_EDGE('',*,*,#409,.T.);
#1265=EDGE_LOOP('',(#1264));
#1266=FACE_BOUND('',#1265,.T.);
#1267=ADVANCED_FACE('F389',(#1263,#1266),#1260,.T.);
#1268=CARTESIAN_POINT('',(49.,0.,42.15));
#1269=DIRECTION('',(0.,0.,1.));
#1270=DIRECTION('',(0.,1.,0.));
#1271=AXIS2_PLACEMENT_3D('',#1268,#1269,#1270);
#1272=CYLINDRICAL_SURFACE('',#1271,5.4375);
#1273=ORIENTED_EDGE('',*,*,#31,.T.);
#1274=EDGE_LOOP('',(#1273));
#1275=FACE_BOUND('',#1274,.T.);
#1276=CARTESIAN_POINT('',(49.,0.,42.3));
#1277=DIRECTION('',(0.,0.,1.));
#1278=DIRECTION('',(0.,1.,0.));
#1279=AXIS2_PLACEMENT_3D('',#1276,#1277,#1278);
#1280=CIRCLE('',#1279,5.4375);
#1281=CARTESIAN_POINT('',(49.,5.43749999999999,42.3));
#1282=VERTEX_POINT('',#1281);
#1283=EDGE_CURVE('E307',#1282,#1282,#1280,.T.);
#1284=ORIENTED_EDGE('',*,*,#1283,.F.);
#1285=EDGE_LOOP('',(#1284));
#1286=FACE_BOUND('',#1285,.T.);
#1287=ADVANCED_FACE('F383',(#1275,#1286),#1272,.T.);
#1288=CARTESIAN_POINT('',(49.,-6.34375,42.3));
#1289=DIRECTION('',(0.,0.,-1.));
#1290=DIRECTION('',(0.,-1.,0.));
#1291=AXIS2_PLACEMENT_3D('',#1288,#1289,#1290);
#1292=PLANE('',#1291);
#1293=CARTESIAN_POINT('',(49.,0.,42.3));
#1294=DIRECTION('',(0.,0.,1.));
#1295=DIRECTION('',(0.,1.,0.));
#1296=AXIS2_PLACEMENT_3D('',#1293,#1294,#1295);
#1297=CIRCLE('',#1296,7.25);
#1298=CARTESIAN_POINT('',(49.,7.24999999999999,42.3));
#1299=VERTEX_POINT('',#1298);
#1300=EDGE_CURVE('E242',#1299,#1299,#1297,.T.);
#1301=ORIENTED_EDGE('',*,*,#1300,.F.);
#1302=EDGE_LOOP('',(#1301));
#1303=FACE_BOUND('',#1302,.T.);
#1304=ORIENTED_EDGE('',*,*,#1283,.T.);
#1305=EDGE_LOOP('',(#1304));
#1306=FACE_BOUND('',#1305,.T.);
#1307=ADVANCED_FACE('F377',(#1303,#1306),#1292,.T.);
#1308=CARTESIAN_POINT('',(49.,0.,51.65));
#1309=DIRECTION('',(0.,0.,1.));
#1310=DIRECTION('',(0.,1.,0.));
#1311=AXIS2_PLACEMENT_3D('',#1308,#1309,#1310);
#1312=CYLINDRICAL_SURFACE('',#1311,7.25);
#1313=ORIENTED_EDGE('',*,*,#1300,.T.);
#1314=EDGE_LOOP('',(#1313));
#1315=FACE_BOUND('',#1314,.T.);
#1316=CARTESIAN_POINT('',(49.,0.,61.));
#1317=DIRECTION('',(0.,0.,-1.));
#1318=DIRECTION('',(1.,0.,0.));
#1319=AXIS2_PLACEMENT_3D('',#1316,#1317,#1318);
#1320=CIRCLE('',#1319,7.25);
#1321=CARTESIAN_POINT('',(56.25,0.,61.));
#1322=VERTEX_POINT('',#1321);
#1323=EDGE_CURVE('E237',#1322,#1322,#1320,.F.);
#1324=ORIENTED_EDGE('',*,*,#1323,.F.);
#1325=EDGE_LOOP('',(#1324));
#1326=FACE_BOUND('',#1325,.T.);
#1327=ADVANCED_FACE('F224',(#1315,#1326),#1312,.T.);
#1328=CARTESIAN_POINT('',(49.,0.,62.75));
#1329=DIRECTION('',(0.,0.,-1.));
#1330=DIRECTION('',(1.,0.,0.));
#1331=AXIS2_PLACEMENT_3D('',#1328,#1329,#1330);
#1332=TOROIDAL_SURFACE('',#1331,7.25,1.75);
#1333=CARTESIAN_POINT('',(49.,0.,62.75));
#1334=DIRECTION('',(0.,0.,1.));
#1335=DIRECTION('',(0.,1.,0.));
#1336=AXIS2_PLACEMENT_3D('',#1333,#1334,#1335);
#1337=CIRCLE('',#1336,9.);
#1338=CARTESIAN_POINT('',(49.,8.99999999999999,62.75));
#1339=VERTEX_POINT('',#1338);
#1340=EDGE_CURVE('E236',#1339,#1339,#1337,.T.);
#1341=ORIENTED_EDGE('',*,*,#1340,.F.);
#1342=EDGE_LOOP('',(#1341));
#1343=FACE_BOUND('',#1342,.T.);
#1344=ORIENTED_EDGE('',*,*,#1323,.T.);
#1345=EDGE_LOOP('',(#1344));
#1346=FACE_BOUND('',#1345,.T.);
#1347=ADVANCED_FACE('F219',(#1343,#1346),#1332,.T.);
#1348=CARTESIAN_POINT('',(49.,0.,77.875));
#1349=DIRECTION('',(0.,0.,1.));
#1350=DIRECTION('',(0.,1.,0.));
#1351=AXIS2_PLACEMENT_3D('',#1348,#1349,#1350);
#1352=CYLINDRICAL_SURFACE('',#1351,9.);
#1353=CARTESIAN_POINT('',(49.,0.,93.));
#1354=DIRECTION('',(0.,0.,1.));
#1355=DIRECTION('',(0.,1.,0.));
#1356=AXIS2_PLACEMENT_3D('',#1353,#1354,#1355);
#1357=CIRCLE('',#1356,9.);
#1358=CARTESIAN_POINT('',(49.,8.99999999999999,93.));
#1359=VERTEX_POINT('',#1358);
#1360=EDGE_CURVE('E233',#1359,#1359,#1357,.F.);
#1361=ORIENTED_EDGE('',*,*,#1360,.T.);
#1362=EDGE_LOOP('',(#1361));
#1363=FACE_BOUND('',#1362,.T.);
#1364=ORIENTED_EDGE('',*,*,#1340,.T.);
#1365=EDGE_LOOP('',(#1364));
#1366=FACE_BOUND('',#1365,.T.);
#1367=ADVANCED_FACE('F216',(#1363,#1366),#1352,.T.);
#1368=CARTESIAN_POINT('',(49.,0.,93.));
#1369=DIRECTION('',(0.,0.,1.));
#1370=DIRECTION('',(0.,-1.,0.));
#1371=AXIS2_PLACEMENT_3D('',#1368,#1369,#1370);
#1372=SPHERICAL_SURFACE('',#1371,9.);
#1373=CARTESIAN_POINT('',(49.,0.,102.));
#1374=VERTEX_POINT('',#1373);
#1375=VERTEX_LOOP('',#1374);
#1376=FACE_BOUND('',#1375,.T.);
#1377=ORIENTED_EDGE('',*,*,#1360,.F.);
#1378=EDGE_LOOP('',(#1377));
#1379=FACE_BOUND('',#1378,.T.);
#1380=ADVANCED_FACE('F211',(#1376,#1379),#1372,.T.);
#1381=CARTESIAN_POINT('',(13.,0.,5.));
#1382=DIRECTION('',(1.,0.,0.));
#1383=DIRECTION('',(0.,0.,-1.));
#1384=AXIS2_PLACEMENT_3D('',#1381,#1382,#1383);
#1385=CYLINDRICAL_SURFACE('',#1384,3.);
#1386=ORIENTED_EDGE('',*,*,#754,.T.);
#1387=EDGE_LOOP('',(#1386));
#1388=FACE_BOUND('',#1387,.T.);
#1389=CARTESIAN_POINT('',(13.,0.,5.));
#1390=DIRECTION('',(-1.,0.,0.));
#1391=DIRECTION('',(0.,0.,1.));
#1392=AXIS2_PLACEMENT_3D('',#1389,#1390,#1391);
#1393=CIRCLE('',#1392,3.);
#1394=CARTESIAN_POINT('',(13.,0.,8.));
#1395=VERTEX_POINT('',#1394);
#1396=EDGE_CURVE('E230',#1395,#1395,#1393,.T.);
#1397=ORIENTED_EDGE('',*,*,#1396,.T.);
#1398=EDGE_LOOP('',(#1397));
#1399=FACE_BOUND('',#1398,.T.);
#1400=ADVANCED_FACE('F206',(#1388,#1399),#1385,.F.);
#1401=CARTESIAN_POINT('',(5.,0.,5.));
#1402=DIRECTION('',(1.,0.,0.));
#1403=DIRECTION('',(0.,0.,-1.));
#1404=AXIS2_PLACEMENT_3D('',#1401,#1402,#1403);
#1405=CYLINDRICAL_SURFACE('',#1404,2.5);
#1406=CARTESIAN_POINT('',(12.7113248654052,0.,5.));
#1407=DIRECTION('',(1.,0.,0.));
#1408=DIRECTION('',(0.,0.,-1.));
#1409=AXIS2_PLACEMENT_3D('',#1406,#1407,#1408);
#1410=CIRCLE('',#1409,2.5);
#1411=CARTESIAN_POINT('',(12.7113248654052,0.,2.5));
#1412=VERTEX_POINT('',#1411);
#1413=EDGE_CURVE('E19',#1412,#1412,#1410,.T.);
#1414=ORIENTED_EDGE('',*,*,#1413,.T.);
#1415=EDGE_LOOP('',(#1414));
#1416=FACE_BOUND('',#1415,.T.);
#1417=ORIENTED_EDGE('',*,*,#943,.F.);
#1418=EDGE_LOOP('',(#1417));
#1419=FACE_BOUND('',#1418,.T.);
#1420=ADVANCED_FACE('F210',(#1416,#1419),#1405,.F.);
#1421=CARTESIAN_POINT('',(11.2679491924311,0.,5.));
#1422=DIRECTION('',(1.,0.,0.));
#1423=DIRECTION('',(0.,0.,-1.));
#1424=AXIS2_PLACEMENT_3D('',#1421,#1422,#1423);
#1425=CONICAL_SURFACE('',#1424,0.,1.0471975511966);
#1426=ORIENTED_EDGE('',*,*,#1396,.F.);
#1427=EDGE_LOOP('',(#1426));
#1428=FACE_BOUND('',#1427,.T.);
#1429=ORIENTED_EDGE('',*,*,#1413,.F.);
#1430=EDGE_LOOP('',(#1429));
#1431=FACE_BOUND('',#1430,.T.);
#1432=ADVANCED_FACE('F761',(#1428,#1431),#1425,.F.);
#1433=CLOSED_SHELL('',(#46,#216,#247,#267,#287,#307,#316,#354,#376,#396,#424,#444,#464,#484,
#515,#535,#555,#575,#595,#615,#627,#647,#667,#772,#792,#812,#832,#852,#961,#981,#1001,#1021,
#1030,#1097,#1128,#1175,#1192,#1209,#1226,#1243,#1255,#1267,#1287,#1307,#1327,#1347,#1367,#1380,
#1400,#1420,#1432));
#1434=CARTESIAN_POINT('',(49.,0.,41.35));
#1435=DIRECTION('',(0.,0.,1.));
#1436=DIRECTION('',(0.,1.,0.));
#1437=AXIS2_PLACEMENT_3D('',#1434,#1435,#1436);
#1438=CYLINDRICAL_SURFACE('',#1437,2.3865);
#1439=CARTESIAN_POINT('',(49.,0.,40.7));
#1440=DIRECTION('',(0.,0.,1.));
#1441=DIRECTION('',(0.,1.,0.));
#1442=AXIS2_PLACEMENT_3D('',#1439,#1440,#1441);
#1443=CIRCLE('',#1442,2.3865);
#1444=CARTESIAN_POINT('',(49.,2.38649999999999,40.7));
#1445=VERTEX_POINT('',#1444);
#1446=EDGE_CURVE('E246',#1445,#1445,#1443,.T.);
#1447=ORIENTED_EDGE('',*,*,#1446,.T.);
#1448=EDGE_LOOP('',(#1447));
#1449=FACE_BOUND('',#1448,.T.);
#1450=CARTESIAN_POINT('',(49.,0.,42.));
#1451=DIRECTION('',(0.,0.,1.));
#1452=DIRECTION('',(0.,1.,0.));
#1453=AXIS2_PLACEMENT_3D('',#1450,#1451,#1452);
#1454=CIRCLE('',#1453,2.3865);
#1455=CARTESIAN_POINT('',(49.,2.38649999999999,42.));
#1456=VERTEX_POINT('',#1455);
#1457=EDGE_CURVE('E249',#1456,#1456,#1454,.T.);
#1458=ORIENTED_EDGE('',*,*,#1457,.F.);
#1459=EDGE_LOOP('',(#1458));
#1460=FACE_BOUND('',#1459,.T.);
#1461=ADVANCED_FACE('F394',(#1449,#1460),#1438,.T.);
#1462=CARTESIAN_POINT('',(49.,-3.912,42.));
#1463=DIRECTION('',(0.,0.,-1.));
#1464=DIRECTION('',(0.,-1.,0.));
#1465=AXIS2_PLACEMENT_3D('',#1462,#1463,#1464);
#1466=PLANE('',#1465);
#1467=ORIENTED_EDGE('',*,*,#1457,.T.);
#1468=EDGE_LOOP('',(#1467));
#1469=FACE_BOUND('',#1468,.T.);
#1470=CARTESIAN_POINT('',(49.,0.,42.));
#1471=DIRECTION('',(0.,0.,-1.));
#1472=DIRECTION('',(0.,-1.,0.));
#1473=AXIS2_PLACEMENT_3D('',#1470,#1471,#1472);
#1474=CIRCLE('',#1473,2.99999999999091);
#1475=CARTESIAN_POINT('',(49.,-2.99999999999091,42.));
#1476=VERTEX_POINT('',#1475);
#1477=EDGE_CURVE('E245',#1476,#1476,#1474,.T.);
#1478=ORIENTED_EDGE('',*,*,#1477,.T.);
#1479=EDGE_LOOP('',(#1478));
#1480=FACE_BOUND('',#1479,.T.);
#1481=ADVANCED_FACE('F391',(#1469,#1480),#1466,.T.);
#1482=CARTESIAN_POINT('',(49.,0.,40.0864999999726));
#1483=DIRECTION('',(0.,0.,-1.));
#1484=DIRECTION('',(0.,-1.,0.));
#1485=AXIS2_PLACEMENT_3D('',#1482,#1483,#1484);
#1486=CONICAL_SURFACE('',#1485,2.99999999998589,0.785398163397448);
#1487=ORIENTED_EDGE('',*,*,#1446,.F.);
#1488=EDGE_LOOP('',(#1487));
#1489=FACE_BOUND('',#1488,.T.);
#1490=CARTESIAN_POINT('',(49.,0.,40.6279999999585));
#1491=DIRECTION('',(0.,0.,-1.));
#1492=DIRECTION('',(0.,-1.,0.));
#1493=AXIS2_PLACEMENT_3D('',#1490,#1491,#1492);
#1494=CIRCLE('',#1493,2.4585);
#1495=CARTESIAN_POINT('',(49.,-2.45850000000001,40.6279999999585));
#1496=VERTEX_POINT('',#1495);
#1497=EDGE_CURVE('E319',#1496,#1496,#1494,.F.);
#1498=ORIENTED_EDGE('',*,*,#1497,.T.);
#1499=EDGE_LOOP('',(#1498));
#1500=FACE_BOUND('',#1499,.T.);
#1501=ADVANCED_FACE('F118',(#1489,#1500),#1486,.T.);
#1502=ORIENTED_EDGE('',*,*,#1497,.F.);
#1503=EDGE_LOOP('',(#1502));
#1504=FACE_BOUND('',#1503,.T.);
#1505=CARTESIAN_POINT('',(49.,0.,41.458500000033));
#1506=DIRECTION('',(0.,0.,1.));
#1507=DIRECTION('',(1.,0.,0.));
#1508=AXIS2_PLACEMENT_3D('',#1505,#1506,#1507);
#1509=CIRCLE('',#1508,2.45850000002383);
#1510=CARTESIAN_POINT('',(51.4585000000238,0.,41.458500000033));
#1511=VERTEX_POINT('',#1510);
#1512=EDGE_CURVE('E58',#1511,#1511,#1509,.T.);
#1513=ORIENTED_EDGE('',*,*,#1512,.T.);
#1514=EDGE_LOOP('',(#1513));
#1515=FACE_BOUND('',#1514,.T.);
#1516=ADVANCED_FACE('F106',(#1504,#1515),#401,.F.);
#1517=CARTESIAN_POINT('',(49.,0.,41.9999999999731));
#1518=DIRECTION('',(0.,0.,1.));
#1519=DIRECTION('',(0.,1.,0.));
#1520=AXIS2_PLACEMENT_3D('',#1517,#1518,#1519);
#1521=CONICAL_SURFACE('',#1520,2.99999999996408,0.785398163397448);
#1522=ORIENTED_EDGE('',*,*,#1477,.F.);
#1523=EDGE_LOOP('',(#1522));
#1524=FACE_BOUND('',#1523,.T.);
#1525=ORIENTED_EDGE('',*,*,#1512,.F.);
#1526=EDGE_LOOP('',(#1525));
#1527=FACE_BOUND('',#1526,.T.);
#1528=ADVANCED_FACE('F88',(#1524,#1527),#1521,.F.);
#1529=CLOSED_SHELL('',(#1461,#1481,#1501,#1516,#1528));
#1530=ORIENTED_CLOSED_SHELL('',*,#1529,.T.);
#1531=BREP_WITH_VOIDS('B1',#1433,(#1530));
#1532=ADVANCED_BREP_SHAPE_REPRESENTATION('',(#18,#1531),#14);
#1533=SHAPE_DEFINITION_REPRESENTATION(#9,#1532);
ENDSEC;
END-ISO-10303-21;
